VERSION 5.7 ;
  NOWIREEXTENSIONATPIN ON ;
  DIVIDERCHAR "/" ;
  BUSBITCHARS "[]" ;
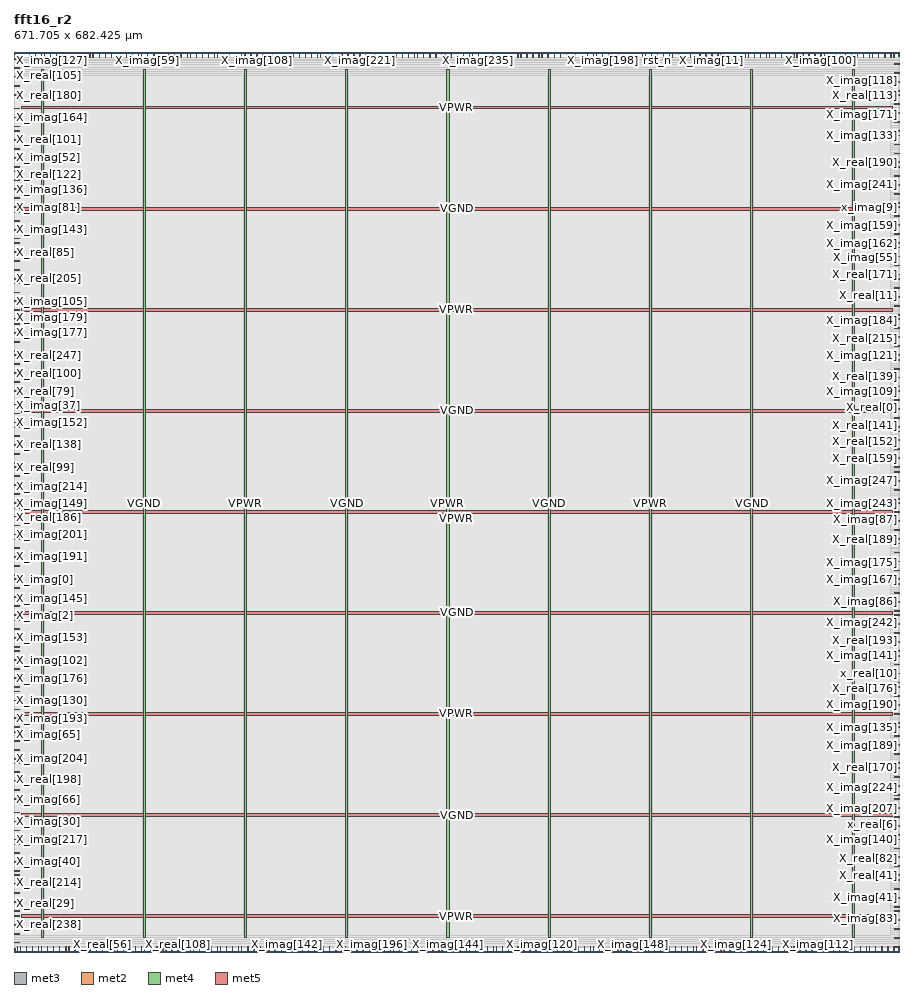
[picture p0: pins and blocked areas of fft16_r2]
MACRO fft16_r2
  CLASS BLOCK ;
  FOREIGN fft16_r2 ;
  ORIGIN 0.000 0.000 ;
  SIZE 671.705 BY 682.425 ;
  PIN X_imag[0]
    DIRECTION OUTPUT TRISTATE ;
    USE SIGNAL ;
    PORT
      LAYER met3 ;
        RECT 0.000 282.240 4.000 282.840 ;
    END
  END X_imag[0]
  PIN X_imag[100]
    DIRECTION OUTPUT TRISTATE ;
    USE SIGNAL ;
    PORT
      LAYER met2 ;
        RECT 611.890 678.425 612.170 682.425 ;
    END
  END X_imag[100]
  PIN X_imag[101]
    DIRECTION OUTPUT TRISTATE ;
    USE SIGNAL ;
    PORT
      LAYER met2 ;
        RECT 138.090 678.425 138.370 682.425 ;
    END
  END X_imag[101]
  PIN X_imag[102]
    DIRECTION OUTPUT TRISTATE ;
    USE SIGNAL ;
    PORT
      LAYER met3 ;
        RECT 0.000 221.040 4.000 221.640 ;
    END
  END X_imag[102]
  PIN X_imag[103]
    DIRECTION OUTPUT TRISTATE ;
    USE SIGNAL ;
    PORT
      LAYER met2 ;
        RECT 602.690 678.425 602.970 682.425 ;
    END
  END X_imag[103]
  PIN X_imag[104]
    DIRECTION OUTPUT TRISTATE ;
    USE SIGNAL ;
    PORT
      LAYER met3 ;
        RECT 667.705 34.040 671.705 34.640 ;
    END
  END X_imag[104]
  PIN X_imag[105]
    DIRECTION OUTPUT TRISTATE ;
    USE SIGNAL ;
    PORT
      LAYER met3 ;
        RECT 0.000 493.040 4.000 493.640 ;
    END
  END X_imag[105]
  PIN X_imag[106]
    DIRECTION OUTPUT TRISTATE ;
    USE SIGNAL ;
    PORT
      LAYER met2 ;
        RECT 154.190 0.000 154.470 4.000 ;
    END
  END X_imag[106]
  PIN X_imag[107]
    DIRECTION OUTPUT TRISTATE ;
    USE SIGNAL ;
    PORT
      LAYER met2 ;
        RECT 526.790 0.000 527.070 4.000 ;
    END
  END X_imag[107]
  PIN X_imag[108]
    DIRECTION OUTPUT TRISTATE ;
    USE SIGNAL ;
    PORT
      LAYER met2 ;
        RECT 184.090 678.425 184.370 682.425 ;
    END
  END X_imag[108]
  PIN X_imag[109]
    DIRECTION OUTPUT TRISTATE ;
    USE SIGNAL ;
    PORT
      LAYER met3 ;
        RECT 667.705 425.040 671.705 425.640 ;
    END
  END X_imag[109]
  PIN X_imag[10]
    DIRECTION OUTPUT TRISTATE ;
    USE SIGNAL ;
    PORT
      LAYER met2 ;
        RECT 204.790 678.425 205.070 682.425 ;
    END
  END X_imag[10]
  PIN X_imag[110]
    DIRECTION OUTPUT TRISTATE ;
    USE SIGNAL ;
    PORT
      LAYER met2 ;
        RECT 151.890 678.425 152.170 682.425 ;
    END
  END X_imag[110]
  PIN X_imag[111]
    DIRECTION OUTPUT TRISTATE ;
    USE SIGNAL ;
    PORT
      LAYER met2 ;
        RECT 218.590 0.000 218.870 4.000 ;
    END
  END X_imag[111]
  PIN X_imag[112]
    DIRECTION OUTPUT TRISTATE ;
    USE SIGNAL ;
    PORT
      LAYER met2 ;
        RECT 609.590 0.000 609.870 4.000 ;
    END
  END X_imag[112]
  PIN X_imag[113]
    DIRECTION OUTPUT TRISTATE ;
    USE SIGNAL ;
    PORT
      LAYER met2 ;
        RECT 225.490 678.425 225.770 682.425 ;
    END
  END X_imag[113]
  PIN X_imag[114]
    DIRECTION OUTPUT TRISTATE ;
    USE SIGNAL ;
    PORT
      LAYER met2 ;
        RECT 646.390 0.000 646.670 4.000 ;
    END
  END X_imag[114]
  PIN X_imag[115]
    DIRECTION OUTPUT TRISTATE ;
    USE SIGNAL ;
    PORT
      LAYER met2 ;
        RECT 96.690 678.425 96.970 682.425 ;
    END
  END X_imag[115]
  PIN X_imag[116]
    DIRECTION OUTPUT TRISTATE ;
    USE SIGNAL ;
    PORT
      LAYER met2 ;
        RECT 236.990 678.425 237.270 682.425 ;
    END
  END X_imag[116]
  PIN X_imag[117]
    DIRECTION OUTPUT TRISTATE ;
    USE SIGNAL ;
    PORT
      LAYER met2 ;
        RECT 476.190 678.425 476.470 682.425 ;
    END
  END X_imag[117]
  PIN X_imag[118]
    DIRECTION OUTPUT TRISTATE ;
    USE SIGNAL ;
    PORT
      LAYER met3 ;
        RECT 667.705 666.440 671.705 667.040 ;
    END
  END X_imag[118]
  PIN X_imag[119]
    DIRECTION OUTPUT TRISTATE ;
    USE SIGNAL ;
    PORT
      LAYER met2 ;
        RECT 430.190 678.425 430.470 682.425 ;
    END
  END X_imag[119]
  PIN X_imag[11]
    DIRECTION OUTPUT TRISTATE ;
    USE SIGNAL ;
    PORT
      LAYER met2 ;
        RECT 529.090 678.425 529.370 682.425 ;
    END
  END X_imag[11]
  PIN X_imag[120]
    DIRECTION OUTPUT TRISTATE ;
    USE SIGNAL ;
    PORT
      LAYER met2 ;
        RECT 400.290 0.000 400.570 4.000 ;
    END
  END X_imag[120]
  PIN X_imag[121]
    DIRECTION OUTPUT TRISTATE ;
    USE SIGNAL ;
    PORT
      LAYER met3 ;
        RECT 667.705 452.240 671.705 452.840 ;
    END
  END X_imag[121]
  PIN X_imag[122]
    DIRECTION OUTPUT TRISTATE ;
    USE SIGNAL ;
    PORT
      LAYER met2 ;
        RECT 515.290 678.425 515.570 682.425 ;
    END
  END X_imag[122]
  PIN X_imag[123]
    DIRECTION OUTPUT TRISTATE ;
    USE SIGNAL ;
    PORT
      LAYER met2 ;
        RECT 554.390 0.000 554.670 4.000 ;
    END
  END X_imag[123]
  PIN X_imag[124]
    DIRECTION OUTPUT TRISTATE ;
    USE SIGNAL ;
    PORT
      LAYER met2 ;
        RECT 547.490 0.000 547.770 4.000 ;
    END
  END X_imag[124]
  PIN X_imag[125]
    DIRECTION OUTPUT TRISTATE ;
    USE SIGNAL ;
    PORT
      LAYER met2 ;
        RECT 499.190 678.425 499.470 682.425 ;
    END
  END X_imag[125]
  PIN X_imag[126]
    DIRECTION OUTPUT TRISTATE ;
    USE SIGNAL ;
    PORT
      LAYER met3 ;
        RECT 667.705 47.640 671.705 48.240 ;
    END
  END X_imag[126]
  PIN X_imag[127]
    DIRECTION OUTPUT TRISTATE ;
    USE SIGNAL ;
    PORT
      LAYER met2 ;
        RECT 16.190 678.425 16.470 682.425 ;
    END
  END X_imag[127]
  PIN X_imag[128]
    DIRECTION OUTPUT TRISTATE ;
    USE SIGNAL ;
    PORT
      LAYER met2 ;
        RECT 439.390 678.425 439.670 682.425 ;
    END
  END X_imag[128]
  PIN X_imag[129]
    DIRECTION OUTPUT TRISTATE ;
    USE SIGNAL ;
    PORT
      LAYER met3 ;
        RECT 667.705 95.240 671.705 95.840 ;
    END
  END X_imag[129]
  PIN X_imag[12]
    DIRECTION OUTPUT TRISTATE ;
    USE SIGNAL ;
    PORT
      LAYER met2 ;
        RECT 2.390 678.425 2.670 682.425 ;
    END
  END X_imag[12]
  PIN X_imag[130]
    DIRECTION OUTPUT TRISTATE ;
    USE SIGNAL ;
    PORT
      LAYER met3 ;
        RECT 0.000 190.440 4.000 191.040 ;
    END
  END X_imag[130]
  PIN X_imag[131]
    DIRECTION OUTPUT TRISTATE ;
    USE SIGNAL ;
    PORT
      LAYER met3 ;
        RECT 0.000 105.440 4.000 106.040 ;
    END
  END X_imag[131]
  PIN X_imag[132]
    DIRECTION OUTPUT TRISTATE ;
    USE SIGNAL ;
    PORT
      LAYER met2 ;
        RECT 496.890 678.425 497.170 682.425 ;
    END
  END X_imag[132]
  PIN X_imag[133]
    DIRECTION OUTPUT TRISTATE ;
    USE SIGNAL ;
    PORT
      LAYER met3 ;
        RECT 667.705 618.840 671.705 619.440 ;
    END
  END X_imag[133]
  PIN X_imag[134]
    DIRECTION OUTPUT TRISTATE ;
    USE SIGNAL ;
    PORT
      LAYER met2 ;
        RECT 255.390 0.000 255.670 4.000 ;
    END
  END X_imag[134]
  PIN X_imag[135]
    DIRECTION OUTPUT TRISTATE ;
    USE SIGNAL ;
    PORT
      LAYER met3 ;
        RECT 667.705 170.040 671.705 170.640 ;
    END
  END X_imag[135]
  PIN X_imag[136]
    DIRECTION OUTPUT TRISTATE ;
    USE SIGNAL ;
    PORT
      LAYER met3 ;
        RECT 0.000 578.040 4.000 578.640 ;
    END
  END X_imag[136]
  PIN X_imag[137]
    DIRECTION OUTPUT TRISTATE ;
    USE SIGNAL ;
    PORT
      LAYER met2 ;
        RECT 572.790 0.000 573.070 4.000 ;
    END
  END X_imag[137]
  PIN X_imag[138]
    DIRECTION OUTPUT TRISTATE ;
    USE SIGNAL ;
    PORT
      LAYER met2 ;
        RECT 167.990 678.425 168.270 682.425 ;
    END
  END X_imag[138]
  PIN X_imag[139]
    DIRECTION OUTPUT TRISTATE ;
    USE SIGNAL ;
    PORT
      LAYER met2 ;
        RECT 190.990 678.425 191.270 682.425 ;
    END
  END X_imag[139]
  PIN X_imag[13]
    DIRECTION OUTPUT TRISTATE ;
    USE SIGNAL ;
    PORT
      LAYER met3 ;
        RECT 667.705 652.840 671.705 653.440 ;
    END
  END X_imag[13]
  PIN X_imag[140]
    DIRECTION OUTPUT TRISTATE ;
    USE SIGNAL ;
    PORT
      LAYER met3 ;
        RECT 667.705 85.040 671.705 85.640 ;
    END
  END X_imag[140]
  PIN X_imag[141]
    DIRECTION OUTPUT TRISTATE ;
    USE SIGNAL ;
    PORT
      LAYER met3 ;
        RECT 667.705 224.440 671.705 225.040 ;
    END
  END X_imag[141]
  PIN X_imag[142]
    DIRECTION OUTPUT TRISTATE ;
    USE SIGNAL ;
    PORT
      LAYER met2 ;
        RECT 207.090 0.000 207.370 4.000 ;
    END
  END X_imag[142]
  PIN X_imag[143]
    DIRECTION OUTPUT TRISTATE ;
    USE SIGNAL ;
    PORT
      LAYER met3 ;
        RECT 0.000 547.440 4.000 548.040 ;
    END
  END X_imag[143]
  PIN X_imag[144]
    DIRECTION OUTPUT TRISTATE ;
    USE SIGNAL ;
    PORT
      LAYER met2 ;
        RECT 328.990 0.000 329.270 4.000 ;
    END
  END X_imag[144]
  PIN X_imag[145]
    DIRECTION OUTPUT TRISTATE ;
    USE SIGNAL ;
    PORT
      LAYER met3 ;
        RECT 0.000 261.840 4.000 262.440 ;
    END
  END X_imag[145]
  PIN X_imag[146]
    DIRECTION OUTPUT TRISTATE ;
    USE SIGNAL ;
    PORT
      LAYER met3 ;
        RECT 667.705 574.640 671.705 575.240 ;
    END
  END X_imag[146]
  PIN X_imag[147]
    DIRECTION OUTPUT TRISTATE ;
    USE SIGNAL ;
    PORT
      LAYER met2 ;
        RECT 230.090 678.425 230.370 682.425 ;
    END
  END X_imag[147]
  PIN X_imag[148]
    DIRECTION OUTPUT TRISTATE ;
    USE SIGNAL ;
    PORT
      LAYER met2 ;
        RECT 469.290 0.000 469.570 4.000 ;
    END
  END X_imag[148]
  PIN X_imag[149]
    DIRECTION OUTPUT TRISTATE ;
    USE SIGNAL ;
    PORT
      LAYER met3 ;
        RECT 0.000 340.040 4.000 340.640 ;
    END
  END X_imag[149]
  PIN X_imag[14]
    DIRECTION OUTPUT TRISTATE ;
    USE SIGNAL ;
    PORT
      LAYER met2 ;
        RECT 425.590 678.425 425.870 682.425 ;
    END
  END X_imag[14]
  PIN X_imag[150]
    DIRECTION OUTPUT TRISTATE ;
    USE SIGNAL ;
    PORT
      LAYER met2 ;
        RECT 627.990 678.425 628.270 682.425 ;
    END
  END X_imag[150]
  PIN X_imag[151]
    DIRECTION OUTPUT TRISTATE ;
    USE SIGNAL ;
    PORT
      LAYER met3 ;
        RECT 667.705 588.240 671.705 588.840 ;
    END
  END X_imag[151]
  PIN X_imag[152]
    DIRECTION OUTPUT TRISTATE ;
    USE SIGNAL ;
    PORT
      LAYER met3 ;
        RECT 0.000 401.240 4.000 401.840 ;
    END
  END X_imag[152]
  PIN X_imag[153]
    DIRECTION OUTPUT TRISTATE ;
    USE SIGNAL ;
    PORT
      LAYER met3 ;
        RECT 0.000 238.040 4.000 238.640 ;
    END
  END X_imag[153]
  PIN X_imag[154]
    DIRECTION OUTPUT TRISTATE ;
    USE SIGNAL ;
    PORT
      LAYER met2 ;
        RECT 32.290 678.425 32.570 682.425 ;
    END
  END X_imag[154]
  PIN X_imag[155]
    DIRECTION OUTPUT TRISTATE ;
    USE SIGNAL ;
    PORT
      LAYER met2 ;
        RECT 248.490 0.000 248.770 4.000 ;
    END
  END X_imag[155]
  PIN X_imag[156]
    DIRECTION OUTPUT TRISTATE ;
    USE SIGNAL ;
    PORT
      LAYER met2 ;
        RECT 496.890 0.000 497.170 4.000 ;
    END
  END X_imag[156]
  PIN X_imag[157]
    DIRECTION OUTPUT TRISTATE ;
    USE SIGNAL ;
    PORT
      LAYER met3 ;
        RECT 0.000 122.440 4.000 123.040 ;
    END
  END X_imag[157]
  PIN X_imag[158]
    DIRECTION OUTPUT TRISTATE ;
    USE SIGNAL ;
    PORT
      LAYER met2 ;
        RECT 133.490 0.000 133.770 4.000 ;
    END
  END X_imag[158]
  PIN X_imag[159]
    DIRECTION OUTPUT TRISTATE ;
    USE SIGNAL ;
    PORT
      LAYER met3 ;
        RECT 667.705 550.840 671.705 551.440 ;
    END
  END X_imag[159]
  PIN X_imag[15]
    DIRECTION OUTPUT TRISTATE ;
    USE SIGNAL ;
    PORT
      LAYER met2 ;
        RECT 6.990 678.425 7.270 682.425 ;
    END
  END X_imag[15]
  PIN X_imag[160]
    DIRECTION OUTPUT TRISTATE ;
    USE SIGNAL ;
    PORT
      LAYER met2 ;
        RECT 614.190 678.425 614.470 682.425 ;
    END
  END X_imag[160]
  PIN X_imag[161]
    DIRECTION OUTPUT TRISTATE ;
    USE SIGNAL ;
    PORT
      LAYER met3 ;
        RECT 667.705 71.440 671.705 72.040 ;
    END
  END X_imag[161]
  PIN X_imag[162]
    DIRECTION OUTPUT TRISTATE ;
    USE SIGNAL ;
    PORT
      LAYER met3 ;
        RECT 667.705 537.240 671.705 537.840 ;
    END
  END X_imag[162]
  PIN X_imag[163]
    DIRECTION OUTPUT TRISTATE ;
    USE SIGNAL ;
    PORT
      LAYER met3 ;
        RECT 667.705 3.440 671.705 4.040 ;
    END
  END X_imag[163]
  PIN X_imag[164]
    DIRECTION OUTPUT TRISTATE ;
    USE SIGNAL ;
    PORT
      LAYER met3 ;
        RECT 0.000 632.440 4.000 633.040 ;
    END
  END X_imag[164]
  PIN X_imag[165]
    DIRECTION OUTPUT TRISTATE ;
    USE SIGNAL ;
    PORT
      LAYER met2 ;
        RECT 540.590 678.425 540.870 682.425 ;
    END
  END X_imag[165]
  PIN X_imag[166]
    DIRECTION OUTPUT TRISTATE ;
    USE SIGNAL ;
    PORT
      LAYER met2 ;
        RECT 494.590 0.000 494.870 4.000 ;
    END
  END X_imag[166]
  PIN X_imag[167]
    DIRECTION OUTPUT TRISTATE ;
    USE SIGNAL ;
    PORT
      LAYER met3 ;
        RECT 667.705 282.240 671.705 282.840 ;
    END
  END X_imag[167]
  PIN X_imag[168]
    DIRECTION OUTPUT TRISTATE ;
    USE SIGNAL ;
    PORT
      LAYER met2 ;
        RECT 418.690 678.425 418.970 682.425 ;
    END
  END X_imag[168]
  PIN X_imag[169]
    DIRECTION OUTPUT TRISTATE ;
    USE SIGNAL ;
    PORT
      LAYER met3 ;
        RECT 667.705 78.240 671.705 78.840 ;
    END
  END X_imag[169]
  PIN X_imag[16]
    DIRECTION OUTPUT TRISTATE ;
    USE SIGNAL ;
    PORT
      LAYER met3 ;
        RECT 667.705 448.840 671.705 449.440 ;
    END
  END X_imag[16]
  PIN X_imag[170]
    DIRECTION OUTPUT TRISTATE ;
    USE SIGNAL ;
    PORT
      LAYER met2 ;
        RECT 568.190 0.000 568.470 4.000 ;
    END
  END X_imag[170]
  PIN X_imag[171]
    DIRECTION OUTPUT TRISTATE ;
    USE SIGNAL ;
    PORT
      LAYER met3 ;
        RECT 667.705 629.040 671.705 629.640 ;
    END
  END X_imag[171]
  PIN X_imag[172]
    DIRECTION OUTPUT TRISTATE ;
    USE SIGNAL ;
    PORT
      LAYER met2 ;
        RECT 158.790 678.425 159.070 682.425 ;
    END
  END X_imag[172]
  PIN X_imag[173]
    DIRECTION OUTPUT TRISTATE ;
    USE SIGNAL ;
    PORT
      LAYER met3 ;
        RECT 667.705 10.240 671.705 10.840 ;
    END
  END X_imag[173]
  PIN X_imag[174]
    DIRECTION OUTPUT TRISTATE ;
    USE SIGNAL ;
    PORT
      LAYER met2 ;
        RECT 664.790 678.425 665.070 682.425 ;
    END
  END X_imag[174]
  PIN X_imag[175]
    DIRECTION OUTPUT TRISTATE ;
    USE SIGNAL ;
    PORT
      LAYER met3 ;
        RECT 667.705 289.040 671.705 289.640 ;
    END
  END X_imag[175]
  PIN X_imag[176]
    DIRECTION OUTPUT TRISTATE ;
    USE SIGNAL ;
    PORT
      LAYER met3 ;
        RECT 0.000 207.440 4.000 208.040 ;
    END
  END X_imag[176]
  PIN X_imag[177]
    DIRECTION OUTPUT TRISTATE ;
    USE SIGNAL ;
    PORT
      LAYER met3 ;
        RECT 0.000 469.240 4.000 469.840 ;
    END
  END X_imag[177]
  PIN X_imag[178]
    DIRECTION OUTPUT TRISTATE ;
    USE SIGNAL ;
    PORT
      LAYER met2 ;
        RECT 20.790 0.000 21.070 4.000 ;
    END
  END X_imag[178]
  PIN X_imag[179]
    DIRECTION OUTPUT TRISTATE ;
    USE SIGNAL ;
    PORT
      LAYER met3 ;
        RECT 0.000 486.240 4.000 486.840 ;
    END
  END X_imag[179]
  PIN X_imag[17]
    DIRECTION OUTPUT TRISTATE ;
    USE SIGNAL ;
    PORT
      LAYER met2 ;
        RECT 257.690 678.425 257.970 682.425 ;
    END
  END X_imag[17]
  PIN X_imag[180]
    DIRECTION OUTPUT TRISTATE ;
    USE SIGNAL ;
    PORT
      LAYER met3 ;
        RECT 667.705 527.040 671.705 527.640 ;
    END
  END X_imag[180]
  PIN X_imag[181]
    DIRECTION OUTPUT TRISTATE ;
    USE SIGNAL ;
    PORT
      LAYER met3 ;
        RECT 0.000 61.240 4.000 61.840 ;
    END
  END X_imag[181]
  PIN X_imag[182]
    DIRECTION OUTPUT TRISTATE ;
    USE SIGNAL ;
    PORT
      LAYER met3 ;
        RECT 667.705 622.240 671.705 622.840 ;
    END
  END X_imag[182]
  PIN X_imag[183]
    DIRECTION OUTPUT TRISTATE ;
    USE SIGNAL ;
    PORT
      LAYER met3 ;
        RECT 0.000 455.640 4.000 456.240 ;
    END
  END X_imag[183]
  PIN X_imag[184]
    DIRECTION OUTPUT TRISTATE ;
    USE SIGNAL ;
    PORT
      LAYER met3 ;
        RECT 667.705 472.640 671.705 473.240 ;
    END
  END X_imag[184]
  PIN X_imag[185]
    DIRECTION OUTPUT TRISTATE ;
    USE SIGNAL ;
    PORT
      LAYER met3 ;
        RECT 667.705 149.640 671.705 150.240 ;
    END
  END X_imag[185]
  PIN X_imag[186]
    DIRECTION OUTPUT TRISTATE ;
    USE SIGNAL ;
    PORT
      LAYER met2 ;
        RECT 230.090 0.000 230.370 4.000 ;
    END
  END X_imag[186]
  PIN X_imag[187]
    DIRECTION OUTPUT TRISTATE ;
    USE SIGNAL ;
    PORT
      LAYER met2 ;
        RECT 356.590 678.425 356.870 682.425 ;
    END
  END X_imag[187]
  PIN X_imag[188]
    DIRECTION OUTPUT TRISTATE ;
    USE SIGNAL ;
    PORT
      LAYER met2 ;
        RECT 241.590 678.425 241.870 682.425 ;
    END
  END X_imag[188]
  PIN X_imag[189]
    DIRECTION OUTPUT TRISTATE ;
    USE SIGNAL ;
    PORT
      LAYER met3 ;
        RECT 667.705 156.440 671.705 157.040 ;
    END
  END X_imag[189]
  PIN X_imag[18]
    DIRECTION OUTPUT TRISTATE ;
    USE SIGNAL ;
    PORT
      LAYER met2 ;
        RECT 20.790 678.425 21.070 682.425 ;
    END
  END X_imag[18]
  PIN X_imag[190]
    DIRECTION OUTPUT TRISTATE ;
    USE SIGNAL ;
    PORT
      LAYER met3 ;
        RECT 667.705 187.040 671.705 187.640 ;
    END
  END X_imag[190]
  PIN X_imag[191]
    DIRECTION OUTPUT TRISTATE ;
    USE SIGNAL ;
    PORT
      LAYER met3 ;
        RECT 0.000 299.240 4.000 299.840 ;
    END
  END X_imag[191]
  PIN X_imag[192]
    DIRECTION OUTPUT TRISTATE ;
    USE SIGNAL ;
    PORT
      LAYER met3 ;
        RECT 0.000 499.840 4.000 500.440 ;
    END
  END X_imag[192]
  PIN X_imag[193]
    DIRECTION OUTPUT TRISTATE ;
    USE SIGNAL ;
    PORT
      LAYER met3 ;
        RECT 0.000 176.840 4.000 177.440 ;
    END
  END X_imag[193]
  PIN X_imag[194]
    DIRECTION OUTPUT TRISTATE ;
    USE SIGNAL ;
    PORT
      LAYER met2 ;
        RECT 69.090 678.425 69.370 682.425 ;
    END
  END X_imag[194]
  PIN X_imag[195]
    DIRECTION OUTPUT TRISTATE ;
    USE SIGNAL ;
    PORT
      LAYER met3 ;
        RECT 667.705 180.240 671.705 180.840 ;
    END
  END X_imag[195]
  PIN X_imag[196]
    DIRECTION OUTPUT TRISTATE ;
    USE SIGNAL ;
    PORT
      LAYER met2 ;
        RECT 271.490 0.000 271.770 4.000 ;
    END
  END X_imag[196]
  PIN X_imag[197]
    DIRECTION OUTPUT TRISTATE ;
    USE SIGNAL ;
    PORT
      LAYER met2 ;
        RECT 464.690 0.000 464.970 4.000 ;
    END
  END X_imag[197]
  PIN X_imag[198]
    DIRECTION OUTPUT TRISTATE ;
    USE SIGNAL ;
    PORT
      LAYER met2 ;
        RECT 446.290 678.425 446.570 682.425 ;
    END
  END X_imag[198]
  PIN X_imag[199]
    DIRECTION OUTPUT TRISTATE ;
    USE SIGNAL ;
    PORT
      LAYER met2 ;
        RECT 453.190 0.000 453.470 4.000 ;
    END
  END X_imag[199]
  PIN X_imag[19]
    DIRECTION OUTPUT TRISTATE ;
    USE SIGNAL ;
    PORT
      LAYER met2 ;
        RECT 397.990 678.425 398.270 682.425 ;
    END
  END X_imag[19]
  PIN X_imag[1]
    DIRECTION OUTPUT TRISTATE ;
    USE SIGNAL ;
    PORT
      LAYER met2 ;
        RECT 634.890 678.425 635.170 682.425 ;
    END
  END X_imag[1]
  PIN X_imag[200]
    DIRECTION OUTPUT TRISTATE ;
    USE SIGNAL ;
    PORT
      LAYER met2 ;
        RECT 512.990 678.425 513.270 682.425 ;
    END
  END X_imag[200]
  PIN X_imag[201]
    DIRECTION OUTPUT TRISTATE ;
    USE SIGNAL ;
    PORT
      LAYER met3 ;
        RECT 0.000 316.240 4.000 316.840 ;
    END
  END X_imag[201]
  PIN X_imag[202]
    DIRECTION OUTPUT TRISTATE ;
    USE SIGNAL ;
    PORT
      LAYER met2 ;
        RECT 13.890 0.000 14.170 4.000 ;
    END
  END X_imag[202]
  PIN X_imag[203]
    DIRECTION OUTPUT TRISTATE ;
    USE SIGNAL ;
    PORT
      LAYER met2 ;
        RECT 4.690 0.000 4.970 4.000 ;
    END
  END X_imag[203]
  PIN X_imag[204]
    DIRECTION OUTPUT TRISTATE ;
    USE SIGNAL ;
    PORT
      LAYER met3 ;
        RECT 0.000 146.240 4.000 146.840 ;
    END
  END X_imag[204]
  PIN X_imag[205]
    DIRECTION OUTPUT TRISTATE ;
    USE SIGNAL ;
    PORT
      LAYER met2 ;
        RECT 269.190 0.000 269.470 4.000 ;
    END
  END X_imag[205]
  PIN X_imag[206]
    DIRECTION OUTPUT TRISTATE ;
    USE SIGNAL ;
    PORT
      LAYER met3 ;
        RECT 0.000 37.440 4.000 38.040 ;
    END
  END X_imag[206]
  PIN X_imag[207]
    DIRECTION OUTPUT TRISTATE ;
    USE SIGNAL ;
    PORT
      LAYER met3 ;
        RECT 667.705 108.840 671.705 109.440 ;
    END
  END X_imag[207]
  PIN X_imag[208]
    DIRECTION OUTPUT TRISTATE ;
    USE SIGNAL ;
    PORT
      LAYER met3 ;
        RECT 667.705 411.440 671.705 412.040 ;
    END
  END X_imag[208]
  PIN X_imag[209]
    DIRECTION OUTPUT TRISTATE ;
    USE SIGNAL ;
    PORT
      LAYER met2 ;
        RECT 115.090 0.000 115.370 4.000 ;
    END
  END X_imag[209]
  PIN X_imag[20]
    DIRECTION OUTPUT TRISTATE ;
    USE SIGNAL ;
    PORT
      LAYER met2 ;
        RECT 161.090 0.000 161.370 4.000 ;
    END
  END X_imag[20]
  PIN X_imag[210]
    DIRECTION OUTPUT TRISTATE ;
    USE SIGNAL ;
    PORT
      LAYER met2 ;
        RECT 195.590 678.425 195.870 682.425 ;
    END
  END X_imag[210]
  PIN X_imag[211]
    DIRECTION OUTPUT TRISTATE ;
    USE SIGNAL ;
    PORT
      LAYER met2 ;
        RECT 420.990 678.425 421.270 682.425 ;
    END
  END X_imag[211]
  PIN X_imag[212]
    DIRECTION OUTPUT TRISTATE ;
    USE SIGNAL ;
    PORT
      LAYER met3 ;
        RECT 667.705 428.440 671.705 429.040 ;
    END
  END X_imag[212]
  PIN X_imag[213]
    DIRECTION OUTPUT TRISTATE ;
    USE SIGNAL ;
    PORT
      LAYER met3 ;
        RECT 0.000 336.640 4.000 337.240 ;
    END
  END X_imag[213]
  PIN X_imag[214]
    DIRECTION OUTPUT TRISTATE ;
    USE SIGNAL ;
    PORT
      LAYER met3 ;
        RECT 0.000 346.840 4.000 347.440 ;
    END
  END X_imag[214]
  PIN X_imag[215]
    DIRECTION OUTPUT TRISTATE ;
    USE SIGNAL ;
    PORT
      LAYER met2 ;
        RECT 117.390 678.425 117.670 682.425 ;
    END
  END X_imag[215]
  PIN X_imag[216]
    DIRECTION OUTPUT TRISTATE ;
    USE SIGNAL ;
    PORT
      LAYER met2 ;
        RECT 549.790 678.425 550.070 682.425 ;
    END
  END X_imag[216]
  PIN X_imag[217]
    DIRECTION OUTPUT TRISTATE ;
    USE SIGNAL ;
    PORT
      LAYER met3 ;
        RECT 0.000 85.040 4.000 85.640 ;
    END
  END X_imag[217]
  PIN X_imag[218]
    DIRECTION OUTPUT TRISTATE ;
    USE SIGNAL ;
    PORT
      LAYER met3 ;
        RECT 0.000 275.440 4.000 276.040 ;
    END
  END X_imag[218]
  PIN X_imag[219]
    DIRECTION OUTPUT TRISTATE ;
    USE SIGNAL ;
    PORT
      LAYER met2 ;
        RECT 558.990 0.000 559.270 4.000 ;
    END
  END X_imag[219]
  PIN X_imag[21]
    DIRECTION OUTPUT TRISTATE ;
    USE SIGNAL ;
    PORT
      LAYER met3 ;
        RECT 667.705 510.040 671.705 510.640 ;
    END
  END X_imag[21]
  PIN X_imag[220]
    DIRECTION OUTPUT TRISTATE ;
    USE SIGNAL ;
    PORT
      LAYER met3 ;
        RECT 0.000 329.840 4.000 330.440 ;
    END
  END X_imag[220]
  PIN X_imag[221]
    DIRECTION OUTPUT TRISTATE ;
    USE SIGNAL ;
    PORT
      LAYER met2 ;
        RECT 262.290 678.425 262.570 682.425 ;
    END
  END X_imag[221]
  PIN X_imag[222]
    DIRECTION OUTPUT TRISTATE ;
    USE SIGNAL ;
    PORT
      LAYER met2 ;
        RECT 259.990 0.000 260.270 4.000 ;
    END
  END X_imag[222]
  PIN X_imag[223]
    DIRECTION OUTPUT TRISTATE ;
    USE SIGNAL ;
    PORT
      LAYER met2 ;
        RECT 324.390 678.425 324.670 682.425 ;
    END
  END X_imag[223]
  PIN X_imag[224]
    DIRECTION OUTPUT TRISTATE ;
    USE SIGNAL ;
    PORT
      LAYER met3 ;
        RECT 667.705 119.040 671.705 119.640 ;
    END
  END X_imag[224]
  PIN X_imag[225]
    DIRECTION OUTPUT TRISTATE ;
    USE SIGNAL ;
    PORT
      LAYER met3 ;
        RECT 667.705 23.840 671.705 24.440 ;
    END
  END X_imag[225]
  PIN X_imag[226]
    DIRECTION OUTPUT TRISTATE ;
    USE SIGNAL ;
    PORT
      LAYER met2 ;
        RECT 188.690 678.425 188.970 682.425 ;
    END
  END X_imag[226]
  PIN X_imag[227]
    DIRECTION OUTPUT TRISTATE ;
    USE SIGNAL ;
    PORT
      LAYER met3 ;
        RECT 667.705 595.040 671.705 595.640 ;
    END
  END X_imag[227]
  PIN X_imag[228]
    DIRECTION OUTPUT TRISTATE ;
    USE SIGNAL ;
    PORT
      LAYER met2 ;
        RECT 384.190 678.425 384.470 682.425 ;
    END
  END X_imag[228]
  PIN X_imag[229]
    DIRECTION OUTPUT TRISTATE ;
    USE SIGNAL ;
    PORT
      LAYER met3 ;
        RECT 0.000 112.240 4.000 112.840 ;
    END
  END X_imag[229]
  PIN X_imag[22]
    DIRECTION OUTPUT TRISTATE ;
    USE SIGNAL ;
    PORT
      LAYER met3 ;
        RECT 0.000 312.840 4.000 313.440 ;
    END
  END X_imag[22]
  PIN X_imag[230]
    DIRECTION OUTPUT TRISTATE ;
    USE SIGNAL ;
    PORT
      LAYER met2 ;
        RECT 25.390 0.000 25.670 4.000 ;
    END
  END X_imag[230]
  PIN X_imag[231]
    DIRECTION OUTPUT TRISTATE ;
    USE SIGNAL ;
    PORT
      LAYER met2 ;
        RECT 455.490 678.425 455.770 682.425 ;
    END
  END X_imag[231]
  PIN X_imag[232]
    DIRECTION OUTPUT TRISTATE ;
    USE SIGNAL ;
    PORT
      LAYER met3 ;
        RECT 667.705 533.840 671.705 534.440 ;
    END
  END X_imag[232]
  PIN X_imag[233]
    DIRECTION OUTPUT TRISTATE ;
    USE SIGNAL ;
    PORT
      LAYER met2 ;
        RECT 285.290 0.000 285.570 4.000 ;
    END
  END X_imag[233]
  PIN X_imag[234]
    DIRECTION OUTPUT TRISTATE ;
    USE SIGNAL ;
    PORT
      LAYER met2 ;
        RECT 317.490 0.000 317.770 4.000 ;
    END
  END X_imag[234]
  PIN X_imag[235]
    DIRECTION OUTPUT TRISTATE ;
    USE SIGNAL ;
    PORT
      LAYER met2 ;
        RECT 351.990 678.425 352.270 682.425 ;
    END
  END X_imag[235]
  PIN X_imag[236]
    DIRECTION OUTPUT TRISTATE ;
    USE SIGNAL ;
    PORT
      LAYER met2 ;
        RECT 407.190 0.000 407.470 4.000 ;
    END
  END X_imag[236]
  PIN X_imag[237]
    DIRECTION OUTPUT TRISTATE ;
    USE SIGNAL ;
    PORT
      LAYER met2 ;
        RECT 2.390 0.000 2.670 4.000 ;
    END
  END X_imag[237]
  PIN X_imag[238]
    DIRECTION OUTPUT TRISTATE ;
    USE SIGNAL ;
    PORT
      LAYER met2 ;
        RECT 46.090 0.000 46.370 4.000 ;
    END
  END X_imag[238]
  PIN X_imag[239]
    DIRECTION OUTPUT TRISTATE ;
    USE SIGNAL ;
    PORT
      LAYER met2 ;
        RECT 96.690 0.000 96.970 4.000 ;
    END
  END X_imag[239]
  PIN X_imag[23]
    DIRECTION OUTPUT TRISTATE ;
    USE SIGNAL ;
    PORT
      LAYER met3 ;
        RECT 0.000 231.240 4.000 231.840 ;
    END
  END X_imag[23]
  PIN X_imag[240]
    DIRECTION OUTPUT TRISTATE ;
    USE SIGNAL ;
    PORT
      LAYER met3 ;
        RECT 0.000 6.840 4.000 7.440 ;
    END
  END X_imag[240]
  PIN X_imag[241]
    DIRECTION OUTPUT TRISTATE ;
    USE SIGNAL ;
    PORT
      LAYER met3 ;
        RECT 667.705 581.440 671.705 582.040 ;
    END
  END X_imag[241]
  PIN X_imag[242]
    DIRECTION OUTPUT TRISTATE ;
    USE SIGNAL ;
    PORT
      LAYER met3 ;
        RECT 667.705 255.040 671.705 255.640 ;
    END
  END X_imag[242]
  PIN X_imag[243]
    DIRECTION OUTPUT TRISTATE ;
    USE SIGNAL ;
    PORT
      LAYER met3 ;
        RECT 667.705 340.040 671.705 340.640 ;
    END
  END X_imag[243]
  PIN X_imag[244]
    DIRECTION OUTPUT TRISTATE ;
    USE SIGNAL ;
    PORT
      LAYER met2 ;
        RECT 73.690 678.425 73.970 682.425 ;
    END
  END X_imag[244]
  PIN X_imag[245]
    DIRECTION OUTPUT TRISTATE ;
    USE SIGNAL ;
    PORT
      LAYER met2 ;
        RECT 630.290 0.000 630.570 4.000 ;
    END
  END X_imag[245]
  PIN X_imag[246]
    DIRECTION OUTPUT TRISTATE ;
    USE SIGNAL ;
    PORT
      LAYER met3 ;
        RECT 667.705 479.440 671.705 480.040 ;
    END
  END X_imag[246]
  PIN X_imag[247]
    DIRECTION OUTPUT TRISTATE ;
    USE SIGNAL ;
    PORT
      LAYER met3 ;
        RECT 667.705 357.040 671.705 357.640 ;
    END
  END X_imag[247]
  PIN X_imag[248]
    DIRECTION OUTPUT TRISTATE ;
    USE SIGNAL ;
    PORT
      LAYER met2 ;
        RECT 211.690 0.000 211.970 4.000 ;
    END
  END X_imag[248]
  PIN X_imag[249]
    DIRECTION OUTPUT TRISTATE ;
    USE SIGNAL ;
    PORT
      LAYER met2 ;
        RECT 448.590 0.000 448.870 4.000 ;
    END
  END X_imag[249]
  PIN X_imag[24]
    DIRECTION OUTPUT TRISTATE ;
    USE SIGNAL ;
    PORT
      LAYER met2 ;
        RECT 200.190 678.425 200.470 682.425 ;
    END
  END X_imag[24]
  PIN X_imag[250]
    DIRECTION OUTPUT TRISTATE ;
    USE SIGNAL ;
    PORT
      LAYER met2 ;
        RECT 595.790 0.000 596.070 4.000 ;
    END
  END X_imag[250]
  PIN X_imag[251]
    DIRECTION OUTPUT TRISTATE ;
    USE SIGNAL ;
    PORT
      LAYER met2 ;
        RECT 331.290 678.425 331.570 682.425 ;
    END
  END X_imag[251]
  PIN X_imag[252]
    DIRECTION OUTPUT TRISTATE ;
    USE SIGNAL ;
    PORT
      LAYER met2 ;
        RECT 437.090 0.000 437.370 4.000 ;
    END
  END X_imag[252]
  PIN X_imag[253]
    DIRECTION OUTPUT TRISTATE ;
    USE SIGNAL ;
    PORT
      LAYER met2 ;
        RECT 319.790 678.425 320.070 682.425 ;
    END
  END X_imag[253]
  PIN X_imag[254]
    DIRECTION OUTPUT TRISTATE ;
    USE SIGNAL ;
    PORT
      LAYER met2 ;
        RECT 342.790 0.000 343.070 4.000 ;
    END
  END X_imag[254]
  PIN X_imag[255]
    DIRECTION OUTPUT TRISTATE ;
    USE SIGNAL ;
    PORT
      LAYER met2 ;
        RECT 607.290 678.425 607.570 682.425 ;
    END
  END X_imag[255]
  PIN X_imag[25]
    DIRECTION OUTPUT TRISTATE ;
    USE SIGNAL ;
    PORT
      LAYER met3 ;
        RECT 0.000 377.440 4.000 378.040 ;
    END
  END X_imag[25]
  PIN X_imag[26]
    DIRECTION OUTPUT TRISTATE ;
    USE SIGNAL ;
    PORT
      LAYER met3 ;
        RECT 0.000 51.040 4.000 51.640 ;
    END
  END X_imag[26]
  PIN X_imag[27]
    DIRECTION OUTPUT TRISTATE ;
    USE SIGNAL ;
    PORT
      LAYER met3 ;
        RECT 0.000 516.840 4.000 517.440 ;
    END
  END X_imag[27]
  PIN X_imag[28]
    DIRECTION OUTPUT TRISTATE ;
    USE SIGNAL ;
    PORT
      LAYER met2 ;
        RECT 333.590 0.000 333.870 4.000 ;
    END
  END X_imag[28]
  PIN X_imag[29]
    DIRECTION OUTPUT TRISTATE ;
    USE SIGNAL ;
    PORT
      LAYER met2 ;
        RECT 48.390 678.425 48.670 682.425 ;
    END
  END X_imag[29]
  PIN X_imag[2]
    DIRECTION OUTPUT TRISTATE ;
    USE SIGNAL ;
    PORT
      LAYER met3 ;
        RECT 0.000 255.040 4.000 255.640 ;
    END
  END X_imag[2]
  PIN X_imag[30]
    DIRECTION OUTPUT TRISTATE ;
    USE SIGNAL ;
    PORT
      LAYER met3 ;
        RECT 0.000 98.640 4.000 99.240 ;
    END
  END X_imag[30]
  PIN X_imag[31]
    DIRECTION OUTPUT TRISTATE ;
    USE SIGNAL ;
    PORT
      LAYER met2 ;
        RECT 301.390 0.000 301.670 4.000 ;
    END
  END X_imag[31]
  PIN X_imag[32]
    DIRECTION OUTPUT TRISTATE ;
    USE SIGNAL ;
    PORT
      LAYER met2 ;
        RECT 623.390 678.425 623.670 682.425 ;
    END
  END X_imag[32]
  PIN X_imag[33]
    DIRECTION OUTPUT TRISTATE ;
    USE SIGNAL ;
    PORT
      LAYER met2 ;
        RECT 473.890 0.000 474.170 4.000 ;
    END
  END X_imag[33]
  PIN X_imag[34]
    DIRECTION OUTPUT TRISTATE ;
    USE SIGNAL ;
    PORT
      LAYER met2 ;
        RECT 466.990 678.425 467.270 682.425 ;
    END
  END X_imag[34]
  PIN X_imag[35]
    DIRECTION OUTPUT TRISTATE ;
    USE SIGNAL ;
    PORT
      LAYER met2 ;
        RECT 517.590 0.000 517.870 4.000 ;
    END
  END X_imag[35]
  PIN X_imag[36]
    DIRECTION OUTPUT TRISTATE ;
    USE SIGNAL ;
    PORT
      LAYER met3 ;
        RECT 667.705 258.440 671.705 259.040 ;
    END
  END X_imag[36]
  PIN X_imag[37]
    DIRECTION OUTPUT TRISTATE ;
    USE SIGNAL ;
    PORT
      LAYER met3 ;
        RECT 0.000 408.040 4.000 408.640 ;
    END
  END X_imag[37]
  PIN X_imag[38]
    DIRECTION OUTPUT TRISTATE ;
    USE SIGNAL ;
    PORT
      LAYER met2 ;
        RECT 457.790 678.425 458.070 682.425 ;
    END
  END X_imag[38]
  PIN X_imag[39]
    DIRECTION OUTPUT TRISTATE ;
    USE SIGNAL ;
    PORT
      LAYER met2 ;
        RECT 232.390 678.425 232.670 682.425 ;
    END
  END X_imag[39]
  PIN X_imag[3]
    DIRECTION OUTPUT TRISTATE ;
    USE SIGNAL ;
    PORT
      LAYER met2 ;
        RECT 584.290 0.000 584.570 4.000 ;
    END
  END X_imag[3]
  PIN X_imag[40]
    DIRECTION OUTPUT TRISTATE ;
    USE SIGNAL ;
    PORT
      LAYER met3 ;
        RECT 0.000 68.040 4.000 68.640 ;
    END
  END X_imag[40]
  PIN X_imag[41]
    DIRECTION OUTPUT TRISTATE ;
    USE SIGNAL ;
    PORT
      LAYER met3 ;
        RECT 667.705 40.840 671.705 41.440 ;
    END
  END X_imag[41]
  PIN X_imag[42]
    DIRECTION OUTPUT TRISTATE ;
    USE SIGNAL ;
    PORT
      LAYER met2 ;
        RECT 80.590 678.425 80.870 682.425 ;
    END
  END X_imag[42]
  PIN X_imag[43]
    DIRECTION OUTPUT TRISTATE ;
    USE SIGNAL ;
    PORT
      LAYER met2 ;
        RECT 126.590 678.425 126.870 682.425 ;
    END
  END X_imag[43]
  PIN X_imag[44]
    DIRECTION OUTPUT TRISTATE ;
    USE SIGNAL ;
    PORT
      LAYER met3 ;
        RECT 0.000 540.640 4.000 541.240 ;
    END
  END X_imag[44]
  PIN X_imag[45]
    DIRECTION OUTPUT TRISTATE ;
    USE SIGNAL ;
    PORT
      LAYER met2 ;
        RECT 121.990 678.425 122.270 682.425 ;
    END
  END X_imag[45]
  PIN X_imag[46]
    DIRECTION OUTPUT TRISTATE ;
    USE SIGNAL ;
    PORT
      LAYER met3 ;
        RECT 0.000 476.040 4.000 476.640 ;
    END
  END X_imag[46]
  PIN X_imag[47]
    DIRECTION OUTPUT TRISTATE ;
    USE SIGNAL ;
    PORT
      LAYER met2 ;
        RECT 611.890 0.000 612.170 4.000 ;
    END
  END X_imag[47]
  PIN X_imag[48]
    DIRECTION OUTPUT TRISTATE ;
    USE SIGNAL ;
    PORT
      LAYER met2 ;
        RECT 381.890 0.000 382.170 4.000 ;
    END
  END X_imag[48]
  PIN X_imag[49]
    DIRECTION OUTPUT TRISTATE ;
    USE SIGNAL ;
    PORT
      LAYER met2 ;
        RECT 340.490 678.425 340.770 682.425 ;
    END
  END X_imag[49]
  PIN X_imag[4]
    DIRECTION OUTPUT TRISTATE ;
    USE SIGNAL ;
    PORT
      LAYER met3 ;
        RECT 667.705 248.240 671.705 248.840 ;
    END
  END X_imag[4]
  PIN X_imag[50]
    DIRECTION OUTPUT TRISTATE ;
    USE SIGNAL ;
    PORT
      LAYER met2 ;
        RECT 216.290 678.425 216.570 682.425 ;
    END
  END X_imag[50]
  PIN X_imag[51]
    DIRECTION OUTPUT TRISTATE ;
    USE SIGNAL ;
    PORT
      LAYER met2 ;
        RECT 462.390 678.425 462.670 682.425 ;
    END
  END X_imag[51]
  PIN X_imag[52]
    DIRECTION OUTPUT TRISTATE ;
    USE SIGNAL ;
    PORT
      LAYER met3 ;
        RECT 0.000 601.840 4.000 602.440 ;
    END
  END X_imag[52]
  PIN X_imag[53]
    DIRECTION OUTPUT TRISTATE ;
    USE SIGNAL ;
    PORT
      LAYER met2 ;
        RECT 287.590 678.425 287.870 682.425 ;
    END
  END X_imag[53]
  PIN X_imag[54]
    DIRECTION OUTPUT TRISTATE ;
    USE SIGNAL ;
    PORT
      LAYER met2 ;
        RECT 372.690 678.425 372.970 682.425 ;
    END
  END X_imag[54]
  PIN X_imag[55]
    DIRECTION OUTPUT TRISTATE ;
    USE SIGNAL ;
    PORT
      LAYER met3 ;
        RECT 667.705 520.240 671.705 520.840 ;
    END
  END X_imag[55]
  PIN X_imag[56]
    DIRECTION OUTPUT TRISTATE ;
    USE SIGNAL ;
    PORT
      LAYER met2 ;
        RECT 565.890 678.425 566.170 682.425 ;
    END
  END X_imag[56]
  PIN X_imag[57]
    DIRECTION OUTPUT TRISTATE ;
    USE SIGNAL ;
    PORT
      LAYER met2 ;
        RECT 326.690 678.425 326.970 682.425 ;
    END
  END X_imag[57]
  PIN X_imag[58]
    DIRECTION OUTPUT TRISTATE ;
    USE SIGNAL ;
    PORT
      LAYER met2 ;
        RECT 105.890 678.425 106.170 682.425 ;
    END
  END X_imag[58]
  PIN X_imag[59]
    DIRECTION OUTPUT TRISTATE ;
    USE SIGNAL ;
    PORT
      LAYER met2 ;
        RECT 101.290 678.425 101.570 682.425 ;
    END
  END X_imag[59]
  PIN X_imag[5]
    DIRECTION OUTPUT TRISTATE ;
    USE SIGNAL ;
    PORT
      LAYER met3 ;
        RECT 0.000 523.640 4.000 524.240 ;
    END
  END X_imag[5]
  PIN X_imag[60]
    DIRECTION OUTPUT TRISTATE ;
    USE SIGNAL ;
    PORT
      LAYER met2 ;
        RECT 570.490 678.425 570.770 682.425 ;
    END
  END X_imag[60]
  PIN X_imag[61]
    DIRECTION OUTPUT TRISTATE ;
    USE SIGNAL ;
    PORT
      LAYER met3 ;
        RECT 0.000 292.440 4.000 293.040 ;
    END
  END X_imag[61]
  PIN X_imag[62]
    DIRECTION OUTPUT TRISTATE ;
    USE SIGNAL ;
    PORT
      LAYER met3 ;
        RECT 667.705 659.640 671.705 660.240 ;
    END
  END X_imag[62]
  PIN X_imag[63]
    DIRECTION OUTPUT TRISTATE ;
    USE SIGNAL ;
    PORT
      LAYER met2 ;
        RECT 172.590 678.425 172.870 682.425 ;
    END
  END X_imag[63]
  PIN X_imag[64]
    DIRECTION OUTPUT TRISTATE ;
    USE SIGNAL ;
    PORT
      LAYER met2 ;
        RECT 57.590 0.000 57.870 4.000 ;
    END
  END X_imag[64]
  PIN X_imag[65]
    DIRECTION OUTPUT TRISTATE ;
    USE SIGNAL ;
    PORT
      LAYER met3 ;
        RECT 0.000 170.040 4.000 170.640 ;
    END
  END X_imag[65]
  PIN X_imag[66]
    DIRECTION OUTPUT TRISTATE ;
    USE SIGNAL ;
    PORT
      LAYER met3 ;
        RECT 0.000 115.640 4.000 116.240 ;
    END
  END X_imag[66]
  PIN X_imag[67]
    DIRECTION OUTPUT TRISTATE ;
    USE SIGNAL ;
    PORT
      LAYER met2 ;
        RECT 39.190 678.425 39.470 682.425 ;
    END
  END X_imag[67]
  PIN X_imag[68]
    DIRECTION OUTPUT TRISTATE ;
    USE SIGNAL ;
    PORT
      LAYER met2 ;
        RECT 358.890 0.000 359.170 4.000 ;
    END
  END X_imag[68]
  PIN X_imag[69]
    DIRECTION OUTPUT TRISTATE ;
    USE SIGNAL ;
    PORT
      LAYER met2 ;
        RECT 223.190 0.000 223.470 4.000 ;
    END
  END X_imag[69]
  PIN X_imag[6]
    DIRECTION OUTPUT TRISTATE ;
    USE SIGNAL ;
    PORT
      LAYER met2 ;
        RECT 363.490 678.425 363.770 682.425 ;
    END
  END X_imag[6]
  PIN X_imag[70]
    DIRECTION OUTPUT TRISTATE ;
    USE SIGNAL ;
    PORT
      LAYER met2 ;
        RECT 92.090 0.000 92.370 4.000 ;
    END
  END X_imag[70]
  PIN X_imag[71]
    DIRECTION OUTPUT TRISTATE ;
    USE SIGNAL ;
    PORT
      LAYER met2 ;
        RECT 657.890 0.000 658.170 4.000 ;
    END
  END X_imag[71]
  PIN X_imag[72]
    DIRECTION OUTPUT TRISTATE ;
    USE SIGNAL ;
    PORT
      LAYER met2 ;
        RECT 23.090 678.425 23.370 682.425 ;
    END
  END X_imag[72]
  PIN X_imag[73]
    DIRECTION OUTPUT TRISTATE ;
    USE SIGNAL ;
    PORT
      LAYER met2 ;
        RECT 404.890 678.425 405.170 682.425 ;
    END
  END X_imag[73]
  PIN X_imag[74]
    DIRECTION OUTPUT TRISTATE ;
    USE SIGNAL ;
    PORT
      LAYER met2 ;
        RECT 276.090 0.000 276.370 4.000 ;
    END
  END X_imag[74]
  PIN X_imag[75]
    DIRECTION OUTPUT TRISTATE ;
    USE SIGNAL ;
    PORT
      LAYER met2 ;
        RECT 388.790 678.425 389.070 682.425 ;
    END
  END X_imag[75]
  PIN X_imag[76]
    DIRECTION OUTPUT TRISTATE ;
    USE SIGNAL ;
    PORT
      LAYER met2 ;
        RECT 186.390 0.000 186.670 4.000 ;
    END
  END X_imag[76]
  PIN X_imag[77]
    DIRECTION OUTPUT TRISTATE ;
    USE SIGNAL ;
    PORT
      LAYER met2 ;
        RECT 43.790 678.425 44.070 682.425 ;
    END
  END X_imag[77]
  PIN X_imag[78]
    DIRECTION OUTPUT TRISTATE ;
    USE SIGNAL ;
    PORT
      LAYER met2 ;
        RECT 110.490 678.425 110.770 682.425 ;
    END
  END X_imag[78]
  PIN X_imag[79]
    DIRECTION OUTPUT TRISTATE ;
    USE SIGNAL ;
    PORT
      LAYER met2 ;
        RECT 492.290 678.425 492.570 682.425 ;
    END
  END X_imag[79]
  PIN X_imag[7]
    DIRECTION OUTPUT TRISTATE ;
    USE SIGNAL ;
    PORT
      LAYER met2 ;
        RECT 489.990 0.000 490.270 4.000 ;
    END
  END X_imag[7]
  PIN X_imag[80]
    DIRECTION OUTPUT TRISTATE ;
    USE SIGNAL ;
    PORT
      LAYER met2 ;
        RECT 234.690 0.000 234.970 4.000 ;
    END
  END X_imag[80]
  PIN X_imag[81]
    DIRECTION OUTPUT TRISTATE ;
    USE SIGNAL ;
    PORT
      LAYER met3 ;
        RECT 0.000 564.440 4.000 565.040 ;
    END
  END X_imag[81]
  PIN X_imag[82]
    DIRECTION OUTPUT TRISTATE ;
    USE SIGNAL ;
    PORT
      LAYER met3 ;
        RECT 0.000 479.440 4.000 480.040 ;
    END
  END X_imag[82]
  PIN X_imag[83]
    DIRECTION OUTPUT TRISTATE ;
    USE SIGNAL ;
    PORT
      LAYER met3 ;
        RECT 667.705 30.640 671.705 31.240 ;
    END
  END X_imag[83]
  PIN X_imag[84]
    DIRECTION OUTPUT TRISTATE ;
    USE SIGNAL ;
    PORT
      LAYER met2 ;
        RECT 593.490 678.425 593.770 682.425 ;
    END
  END X_imag[84]
  PIN X_imag[85]
    DIRECTION OUTPUT TRISTATE ;
    USE SIGNAL ;
    PORT
      LAYER met2 ;
        RECT 554.390 678.425 554.670 682.425 ;
    END
  END X_imag[85]
  PIN X_imag[86]
    DIRECTION OUTPUT TRISTATE ;
    USE SIGNAL ;
    PORT
      LAYER met3 ;
        RECT 667.705 265.240 671.705 265.840 ;
    END
  END X_imag[86]
  PIN X_imag[87]
    DIRECTION OUTPUT TRISTATE ;
    USE SIGNAL ;
    PORT
      LAYER met3 ;
        RECT 667.705 333.240 671.705 333.840 ;
    END
  END X_imag[87]
  PIN X_imag[88]
    DIRECTION OUTPUT TRISTATE ;
    USE SIGNAL ;
    PORT
      LAYER met2 ;
        RECT 147.290 678.425 147.570 682.425 ;
    END
  END X_imag[88]
  PIN X_imag[89]
    DIRECTION OUTPUT TRISTATE ;
    USE SIGNAL ;
    PORT
      LAYER met2 ;
        RECT 227.790 0.000 228.070 4.000 ;
    END
  END X_imag[89]
  PIN X_imag[8]
    DIRECTION OUTPUT TRISTATE ;
    USE SIGNAL ;
    PORT
      LAYER met2 ;
        RECT 460.090 0.000 460.370 4.000 ;
    END
  END X_imag[8]
  PIN X_imag[90]
    DIRECTION OUTPUT TRISTATE ;
    USE SIGNAL ;
    PORT
      LAYER met2 ;
        RECT 432.490 0.000 432.770 4.000 ;
    END
  END X_imag[90]
  PIN X_imag[91]
    DIRECTION OUTPUT TRISTATE ;
    USE SIGNAL ;
    PORT
      LAYER met3 ;
        RECT 667.705 557.640 671.705 558.240 ;
    END
  END X_imag[91]
  PIN X_imag[92]
    DIRECTION OUTPUT TRISTATE ;
    USE SIGNAL ;
    PORT
      LAYER met2 ;
        RECT 377.290 678.425 377.570 682.425 ;
    END
  END X_imag[92]
  PIN X_imag[93]
    DIRECTION OUTPUT TRISTATE ;
    USE SIGNAL ;
    PORT
      LAYER met2 ;
        RECT 87.490 0.000 87.770 4.000 ;
    END
  END X_imag[93]
  PIN X_imag[94]
    DIRECTION OUTPUT TRISTATE ;
    USE SIGNAL ;
    PORT
      LAYER met3 ;
        RECT 0.000 166.640 4.000 167.240 ;
    END
  END X_imag[94]
  PIN X_imag[95]
    DIRECTION OUTPUT TRISTATE ;
    USE SIGNAL ;
    PORT
      LAYER met3 ;
        RECT 0.000 360.440 4.000 361.040 ;
    END
  END X_imag[95]
  PIN X_imag[96]
    DIRECTION OUTPUT TRISTATE ;
    USE SIGNAL ;
    PORT
      LAYER met2 ;
        RECT 381.890 678.425 382.170 682.425 ;
    END
  END X_imag[96]
  PIN X_imag[97]
    DIRECTION OUTPUT TRISTATE ;
    USE SIGNAL ;
    PORT
      LAYER met2 ;
        RECT 149.590 0.000 149.870 4.000 ;
    END
  END X_imag[97]
  PIN X_imag[98]
    DIRECTION OUTPUT TRISTATE ;
    USE SIGNAL ;
    PORT
      LAYER met3 ;
        RECT 0.000 159.840 4.000 160.440 ;
    END
  END X_imag[98]
  PIN X_imag[99]
    DIRECTION OUTPUT TRISTATE ;
    USE SIGNAL ;
    PORT
      LAYER met2 ;
        RECT 522.190 0.000 522.470 4.000 ;
    END
  END X_imag[99]
  PIN X_imag[9]
    DIRECTION OUTPUT TRISTATE ;
    USE SIGNAL ;
    PORT
      LAYER met2 ;
        RECT 59.890 678.425 60.170 682.425 ;
    END
  END X_imag[9]
  PIN X_real[0]
    DIRECTION OUTPUT TRISTATE ;
    USE SIGNAL ;
    PORT
      LAYER met3 ;
        RECT 667.705 418.240 671.705 418.840 ;
    END
  END X_real[0]
  PIN X_real[100]
    DIRECTION OUTPUT TRISTATE ;
    USE SIGNAL ;
    PORT
      LAYER met3 ;
        RECT 0.000 438.640 4.000 439.240 ;
    END
  END X_real[100]
  PIN X_real[101]
    DIRECTION OUTPUT TRISTATE ;
    USE SIGNAL ;
    PORT
      LAYER met3 ;
        RECT 0.000 615.440 4.000 616.040 ;
    END
  END X_real[101]
  PIN X_real[102]
    DIRECTION OUTPUT TRISTATE ;
    USE SIGNAL ;
    PORT
      LAYER met3 ;
        RECT 667.705 132.640 671.705 133.240 ;
    END
  END X_real[102]
  PIN X_real[103]
    DIRECTION OUTPUT TRISTATE ;
    USE SIGNAL ;
    PORT
      LAYER met2 ;
        RECT 299.090 678.425 299.370 682.425 ;
    END
  END X_real[103]
  PIN X_real[104]
    DIRECTION OUTPUT TRISTATE ;
    USE SIGNAL ;
    PORT
      LAYER met2 ;
        RECT 478.490 0.000 478.770 4.000 ;
    END
  END X_real[104]
  PIN X_real[105]
    DIRECTION OUTPUT TRISTATE ;
    USE SIGNAL ;
    PORT
      LAYER met3 ;
        RECT 0.000 669.840 4.000 670.440 ;
    END
  END X_real[105]
  PIN X_real[106]
    DIRECTION OUTPUT TRISTATE ;
    USE SIGNAL ;
    PORT
      LAYER met2 ;
        RECT 443.990 0.000 444.270 4.000 ;
    END
  END X_real[106]
  PIN X_real[107]
    DIRECTION OUTPUT TRISTATE ;
    USE SIGNAL ;
    PORT
      LAYER met3 ;
        RECT 0.000 197.240 4.000 197.840 ;
    END
  END X_real[107]
  PIN X_real[108]
    DIRECTION OUTPUT TRISTATE ;
    USE SIGNAL ;
    PORT
      LAYER met2 ;
        RECT 124.290 0.000 124.570 4.000 ;
    END
  END X_real[108]
  PIN X_real[109]
    DIRECTION OUTPUT TRISTATE ;
    USE SIGNAL ;
    PORT
      LAYER met2 ;
        RECT 89.790 678.425 90.070 682.425 ;
    END
  END X_real[109]
  PIN X_real[10]
    DIRECTION OUTPUT TRISTATE ;
    USE SIGNAL ;
    PORT
      LAYER met2 ;
        RECT 273.790 678.425 274.070 682.425 ;
    END
  END X_real[10]
  PIN X_real[110]
    DIRECTION OUTPUT TRISTATE ;
    USE SIGNAL ;
    PORT
      LAYER met2 ;
        RECT 531.390 0.000 531.670 4.000 ;
    END
  END X_real[110]
  PIN X_real[111]
    DIRECTION OUTPUT TRISTATE ;
    USE SIGNAL ;
    PORT
      LAYER met2 ;
        RECT 71.390 0.000 71.670 4.000 ;
    END
  END X_real[111]
  PIN X_real[112]
    DIRECTION OUTPUT TRISTATE ;
    USE SIGNAL ;
    PORT
      LAYER met2 ;
        RECT 278.390 678.425 278.670 682.425 ;
    END
  END X_real[112]
  PIN X_real[113]
    DIRECTION OUTPUT TRISTATE ;
    USE SIGNAL ;
    PORT
      LAYER met3 ;
        RECT 667.705 649.440 671.705 650.040 ;
    END
  END X_real[113]
  PIN X_real[114]
    DIRECTION OUTPUT TRISTATE ;
    USE SIGNAL ;
    PORT
      LAYER met2 ;
        RECT 524.490 678.425 524.770 682.425 ;
    END
  END X_real[114]
  PIN X_real[115]
    DIRECTION OUTPUT TRISTATE ;
    USE SIGNAL ;
    PORT
      LAYER met2 ;
        RECT 591.190 678.425 591.470 682.425 ;
    END
  END X_real[115]
  PIN X_real[116]
    DIRECTION OUTPUT TRISTATE ;
    USE SIGNAL ;
    PORT
      LAYER met3 ;
        RECT 0.000 445.440 4.000 446.040 ;
    END
  END X_real[116]
  PIN X_real[117]
    DIRECTION OUTPUT TRISTATE ;
    USE SIGNAL ;
    PORT
      LAYER met2 ;
        RECT 209.390 678.425 209.670 682.425 ;
    END
  END X_real[117]
  PIN X_real[118]
    DIRECTION OUTPUT TRISTATE ;
    USE SIGNAL ;
    PORT
      LAYER met2 ;
        RECT 193.290 0.000 193.570 4.000 ;
    END
  END X_real[118]
  PIN X_real[119]
    DIRECTION OUTPUT TRISTATE ;
    USE SIGNAL ;
    PORT
      LAYER met3 ;
        RECT 0.000 183.640 4.000 184.240 ;
    END
  END X_real[119]
  PIN X_real[11]
    DIRECTION OUTPUT TRISTATE ;
    USE SIGNAL ;
    PORT
      LAYER met3 ;
        RECT 667.705 503.240 671.705 503.840 ;
    END
  END X_real[11]
  PIN X_real[120]
    DIRECTION OUTPUT TRISTATE ;
    USE SIGNAL ;
    PORT
      LAYER met2 ;
        RECT 572.790 678.425 573.070 682.425 ;
    END
  END X_real[120]
  PIN X_real[121]
    DIRECTION OUTPUT TRISTATE ;
    USE SIGNAL ;
    PORT
      LAYER met3 ;
        RECT 0.000 676.640 4.000 677.240 ;
    END
  END X_real[121]
  PIN X_real[122]
    DIRECTION OUTPUT TRISTATE ;
    USE SIGNAL ;
    PORT
      LAYER met3 ;
        RECT 0.000 595.040 4.000 595.640 ;
    END
  END X_real[122]
  PIN X_real[123]
    DIRECTION OUTPUT TRISTATE ;
    USE SIGNAL ;
    PORT
      LAYER met3 ;
        RECT 0.000 27.240 4.000 27.840 ;
    END
  END X_real[123]
  PIN X_real[124]
    DIRECTION OUTPUT TRISTATE ;
    USE SIGNAL ;
    PORT
      LAYER met2 ;
        RECT 402.590 0.000 402.870 4.000 ;
    END
  END X_real[124]
  PIN X_real[125]
    DIRECTION OUTPUT TRISTATE ;
    USE SIGNAL ;
    PORT
      LAYER met2 ;
        RECT 57.590 678.425 57.870 682.425 ;
    END
  END X_real[125]
  PIN X_real[126]
    DIRECTION OUTPUT TRISTATE ;
    USE SIGNAL ;
    PORT
      LAYER met2 ;
        RECT 441.690 678.425 441.970 682.425 ;
    END
  END X_real[126]
  PIN X_real[127]
    DIRECTION OUTPUT TRISTATE ;
    USE SIGNAL ;
    PORT
      LAYER met2 ;
        RECT 506.090 0.000 506.370 4.000 ;
    END
  END X_real[127]
  PIN X_real[128]
    DIRECTION OUTPUT TRISTATE ;
    USE SIGNAL ;
    PORT
      LAYER met2 ;
        RECT 197.890 0.000 198.170 4.000 ;
    END
  END X_real[128]
  PIN X_real[129]
    DIRECTION OUTPUT TRISTATE ;
    USE SIGNAL ;
    PORT
      LAYER met2 ;
        RECT 94.390 678.425 94.670 682.425 ;
    END
  END X_real[129]
  PIN X_real[12]
    DIRECTION OUTPUT TRISTATE ;
    USE SIGNAL ;
    PORT
      LAYER met3 ;
        RECT 0.000 561.040 4.000 561.640 ;
    END
  END X_real[12]
  PIN X_real[130]
    DIRECTION OUTPUT TRISTATE ;
    USE SIGNAL ;
    PORT
      LAYER met2 ;
        RECT 248.490 678.425 248.770 682.425 ;
    END
  END X_real[130]
  PIN X_real[131]
    DIRECTION OUTPUT TRISTATE ;
    USE SIGNAL ;
    PORT
      LAYER met3 ;
        RECT 0.000 214.240 4.000 214.840 ;
    END
  END X_real[131]
  PIN X_real[132]
    DIRECTION OUTPUT TRISTATE ;
    USE SIGNAL ;
    PORT
      LAYER met3 ;
        RECT 667.705 54.440 671.705 55.040 ;
    END
  END X_real[132]
  PIN X_real[133]
    DIRECTION OUTPUT TRISTATE ;
    USE SIGNAL ;
    PORT
      LAYER met2 ;
        RECT 660.190 678.425 660.470 682.425 ;
    END
  END X_real[133]
  PIN X_real[134]
    DIRECTION OUTPUT TRISTATE ;
    USE SIGNAL ;
    PORT
      LAYER met2 ;
        RECT 239.290 0.000 239.570 4.000 ;
    END
  END X_real[134]
  PIN X_real[135]
    DIRECTION OUTPUT TRISTATE ;
    USE SIGNAL ;
    PORT
      LAYER met3 ;
        RECT 667.705 173.440 671.705 174.040 ;
    END
  END X_real[135]
  PIN X_real[136]
    DIRECTION OUTPUT TRISTATE ;
    USE SIGNAL ;
    PORT
      LAYER met2 ;
        RECT 98.990 0.000 99.270 4.000 ;
    END
  END X_real[136]
  PIN X_real[137]
    DIRECTION OUTPUT TRISTATE ;
    USE SIGNAL ;
    PORT
      LAYER met3 ;
        RECT 0.000 153.040 4.000 153.640 ;
    END
  END X_real[137]
  PIN X_real[138]
    DIRECTION OUTPUT TRISTATE ;
    USE SIGNAL ;
    PORT
      LAYER met3 ;
        RECT 0.000 384.240 4.000 384.840 ;
    END
  END X_real[138]
  PIN X_real[139]
    DIRECTION OUTPUT TRISTATE ;
    USE SIGNAL ;
    PORT
      LAYER met3 ;
        RECT 667.705 442.040 671.705 442.640 ;
    END
  END X_real[139]
  PIN X_real[13]
    DIRECTION OUTPUT TRISTATE ;
    USE SIGNAL ;
    PORT
      LAYER met2 ;
        RECT 213.990 0.000 214.270 4.000 ;
    END
  END X_real[13]
  PIN X_real[140]
    DIRECTION OUTPUT TRISTATE ;
    USE SIGNAL ;
    PORT
      LAYER met2 ;
        RECT 305.990 0.000 306.270 4.000 ;
    END
  END X_real[140]
  PIN X_real[141]
    DIRECTION OUTPUT TRISTATE ;
    USE SIGNAL ;
    PORT
      LAYER met3 ;
        RECT 667.705 404.640 671.705 405.240 ;
    END
  END X_real[141]
  PIN X_real[142]
    DIRECTION OUTPUT TRISTATE ;
    USE SIGNAL ;
    PORT
      LAYER met2 ;
        RECT 393.390 678.425 393.670 682.425 ;
    END
  END X_real[142]
  PIN X_real[143]
    DIRECTION OUTPUT TRISTATE ;
    USE SIGNAL ;
    PORT
      LAYER met2 ;
        RECT 131.190 678.425 131.470 682.425 ;
    END
  END X_real[143]
  PIN X_real[144]
    DIRECTION OUTPUT TRISTATE ;
    USE SIGNAL ;
    PORT
      LAYER met3 ;
        RECT 0.000 13.640 4.000 14.240 ;
    END
  END X_real[144]
  PIN X_real[145]
    DIRECTION OUTPUT TRISTATE ;
    USE SIGNAL ;
    PORT
      LAYER met2 ;
        RECT 411.790 0.000 412.070 4.000 ;
    END
  END X_real[145]
  PIN X_real[146]
    DIRECTION OUTPUT TRISTATE ;
    USE SIGNAL ;
    PORT
      LAYER met3 ;
        RECT 0.000 646.040 4.000 646.640 ;
    END
  END X_real[146]
  PIN X_real[147]
    DIRECTION OUTPUT TRISTATE ;
    USE SIGNAL ;
    PORT
      LAYER met2 ;
        RECT 386.490 0.000 386.770 4.000 ;
    END
  END X_real[147]
  PIN X_real[148]
    DIRECTION OUTPUT TRISTATE ;
    USE SIGNAL ;
    PORT
      LAYER met3 ;
        RECT 667.705 272.040 671.705 272.640 ;
    END
  END X_real[148]
  PIN X_real[149]
    DIRECTION OUTPUT TRISTATE ;
    USE SIGNAL ;
    PORT
      LAYER met2 ;
        RECT 535.990 0.000 536.270 4.000 ;
    END
  END X_real[149]
  PIN X_real[14]
    DIRECTION OUTPUT TRISTATE ;
    USE SIGNAL ;
    PORT
      LAYER met2 ;
        RECT 289.890 678.425 290.170 682.425 ;
    END
  END X_real[14]
  PIN X_real[150]
    DIRECTION OUTPUT TRISTATE ;
    USE SIGNAL ;
    PORT
      LAYER met3 ;
        RECT 667.705 394.440 671.705 395.040 ;
    END
  END X_real[150]
  PIN X_real[151]
    DIRECTION OUTPUT TRISTATE ;
    USE SIGNAL ;
    PORT
      LAYER met2 ;
        RECT 347.390 678.425 347.670 682.425 ;
    END
  END X_real[151]
  PIN X_real[152]
    DIRECTION OUTPUT TRISTATE ;
    USE SIGNAL ;
    PORT
      LAYER met3 ;
        RECT 667.705 380.840 671.705 381.440 ;
    END
  END X_real[152]
  PIN X_real[153]
    DIRECTION OUTPUT TRISTATE ;
    USE SIGNAL ;
    PORT
      LAYER met2 ;
        RECT 598.090 678.425 598.370 682.425 ;
    END
  END X_real[153]
  PIN X_real[154]
    DIRECTION OUTPUT TRISTATE ;
    USE SIGNAL ;
    PORT
      LAYER met2 ;
        RECT 648.690 678.425 648.970 682.425 ;
    END
  END X_real[154]
  PIN X_real[155]
    DIRECTION OUTPUT TRISTATE ;
    USE SIGNAL ;
    PORT
      LAYER met2 ;
        RECT 391.090 0.000 391.370 4.000 ;
    END
  END X_real[155]
  PIN X_real[156]
    DIRECTION OUTPUT TRISTATE ;
    USE SIGNAL ;
    PORT
      LAYER met2 ;
        RECT 450.890 678.425 451.170 682.425 ;
    END
  END X_real[156]
  PIN X_real[157]
    DIRECTION OUTPUT TRISTATE ;
    USE SIGNAL ;
    PORT
      LAYER met3 ;
        RECT 0.000 142.840 4.000 143.440 ;
    END
  END X_real[157]
  PIN X_real[158]
    DIRECTION OUTPUT TRISTATE ;
    USE SIGNAL ;
    PORT
      LAYER met2 ;
        RECT 653.290 0.000 653.570 4.000 ;
    END
  END X_real[158]
  PIN X_real[159]
    DIRECTION OUTPUT TRISTATE ;
    USE SIGNAL ;
    PORT
      LAYER met3 ;
        RECT 667.705 374.040 671.705 374.640 ;
    END
  END X_real[159]
  PIN X_real[15]
    DIRECTION OUTPUT TRISTATE ;
    USE SIGNAL ;
    PORT
      LAYER met2 ;
        RECT 354.290 0.000 354.570 4.000 ;
    END
  END X_real[15]
  PIN X_real[160]
    DIRECTION OUTPUT TRISTATE ;
    USE SIGNAL ;
    PORT
      LAYER met3 ;
        RECT 0.000 306.040 4.000 306.640 ;
    END
  END X_real[160]
  PIN X_real[161]
    DIRECTION OUTPUT TRISTATE ;
    USE SIGNAL ;
    PORT
      LAYER met2 ;
        RECT 36.890 678.425 37.170 682.425 ;
    END
  END X_real[161]
  PIN X_real[162]
    DIRECTION OUTPUT TRISTATE ;
    USE SIGNAL ;
    PORT
      LAYER met2 ;
        RECT 312.890 0.000 313.170 4.000 ;
    END
  END X_real[162]
  PIN X_real[163]
    DIRECTION OUTPUT TRISTATE ;
    USE SIGNAL ;
    PORT
      LAYER met3 ;
        RECT 667.705 489.640 671.705 490.240 ;
    END
  END X_real[163]
  PIN X_real[164]
    DIRECTION OUTPUT TRISTATE ;
    USE SIGNAL ;
    PORT
      LAYER met3 ;
        RECT 667.705 635.840 671.705 636.440 ;
    END
  END X_real[164]
  PIN X_real[165]
    DIRECTION OUTPUT TRISTATE ;
    USE SIGNAL ;
    PORT
      LAYER met3 ;
        RECT 0.000 81.640 4.000 82.240 ;
    END
  END X_real[165]
  PIN X_real[166]
    DIRECTION OUTPUT TRISTATE ;
    USE SIGNAL ;
    PORT
      LAYER met3 ;
        RECT 667.705 482.840 671.705 483.440 ;
    END
  END X_real[166]
  PIN X_real[167]
    DIRECTION OUTPUT TRISTATE ;
    USE SIGNAL ;
    PORT
      LAYER met2 ;
        RECT 296.790 0.000 297.070 4.000 ;
    END
  END X_real[167]
  PIN X_real[168]
    DIRECTION OUTPUT TRISTATE ;
    USE SIGNAL ;
    PORT
      LAYER met2 ;
        RECT 163.390 678.425 163.670 682.425 ;
    END
  END X_real[168]
  PIN X_real[169]
    DIRECTION OUTPUT TRISTATE ;
    USE SIGNAL ;
    PORT
      LAYER met3 ;
        RECT 0.000 625.640 4.000 626.240 ;
    END
  END X_real[169]
  PIN X_real[16]
    DIRECTION OUTPUT TRISTATE ;
    USE SIGNAL ;
    PORT
      LAYER met3 ;
        RECT 667.705 163.240 671.705 163.840 ;
    END
  END X_real[16]
  PIN X_real[170]
    DIRECTION OUTPUT TRISTATE ;
    USE SIGNAL ;
    PORT
      LAYER met3 ;
        RECT 667.705 139.440 671.705 140.040 ;
    END
  END X_real[170]
  PIN X_real[171]
    DIRECTION OUTPUT TRISTATE ;
    USE SIGNAL ;
    PORT
      LAYER met3 ;
        RECT 667.705 513.440 671.705 514.040 ;
    END
  END X_real[171]
  PIN X_real[172]
    DIRECTION OUTPUT TRISTATE ;
    USE SIGNAL ;
    PORT
      LAYER met3 ;
        RECT 0.000 506.640 4.000 507.240 ;
    END
  END X_real[172]
  PIN X_real[173]
    DIRECTION OUTPUT TRISTATE ;
    USE SIGNAL ;
    PORT
      LAYER met3 ;
        RECT 667.705 397.840 671.705 398.440 ;
    END
  END X_real[173]
  PIN X_real[174]
    DIRECTION OUTPUT TRISTATE ;
    USE SIGNAL ;
    PORT
      LAYER met3 ;
        RECT 667.705 326.440 671.705 327.040 ;
    END
  END X_real[174]
  PIN X_real[175]
    DIRECTION OUTPUT TRISTATE ;
    USE SIGNAL ;
    PORT
      LAYER met2 ;
        RECT 641.790 0.000 642.070 4.000 ;
    END
  END X_real[175]
  PIN X_real[176]
    DIRECTION OUTPUT TRISTATE ;
    USE SIGNAL ;
    PORT
      LAYER met3 ;
        RECT 667.705 193.840 671.705 194.440 ;
    END
  END X_real[176]
  PIN X_real[177]
    DIRECTION OUTPUT TRISTATE ;
    USE SIGNAL ;
    PORT
      LAYER met3 ;
        RECT 667.705 387.640 671.705 388.240 ;
    END
  END X_real[177]
  PIN X_real[178]
    DIRECTION OUTPUT TRISTATE ;
    USE SIGNAL ;
    PORT
      LAYER met2 ;
        RECT 591.190 0.000 591.470 4.000 ;
    END
  END X_real[178]
  PIN X_real[179]
    DIRECTION OUTPUT TRISTATE ;
    USE SIGNAL ;
    PORT
      LAYER met2 ;
        RECT 308.290 0.000 308.570 4.000 ;
    END
  END X_real[179]
  PIN X_real[17]
    DIRECTION OUTPUT TRISTATE ;
    USE SIGNAL ;
    PORT
      LAYER met2 ;
        RECT 400.290 678.425 400.570 682.425 ;
    END
  END X_real[17]
  PIN X_real[180]
    DIRECTION OUTPUT TRISTATE ;
    USE SIGNAL ;
    PORT
      LAYER met3 ;
        RECT 0.000 649.440 4.000 650.040 ;
    END
  END X_real[180]
  PIN X_real[181]
    DIRECTION OUTPUT TRISTATE ;
    USE SIGNAL ;
    PORT
      LAYER met2 ;
        RECT 503.790 678.425 504.070 682.425 ;
    END
  END X_real[181]
  PIN X_real[182]
    DIRECTION OUTPUT TRISTATE ;
    USE SIGNAL ;
    PORT
      LAYER met2 ;
        RECT 508.390 678.425 508.670 682.425 ;
    END
  END X_real[182]
  PIN X_real[183]
    DIRECTION OUTPUT TRISTATE ;
    USE SIGNAL ;
    PORT
      LAYER met2 ;
        RECT 423.290 0.000 423.570 4.000 ;
    END
  END X_real[183]
  PIN X_real[184]
    DIRECTION OUTPUT TRISTATE ;
    USE SIGNAL ;
    PORT
      LAYER met2 ;
        RECT 243.890 0.000 244.170 4.000 ;
    END
  END X_real[184]
  PIN X_real[185]
    DIRECTION OUTPUT TRISTATE ;
    USE SIGNAL ;
    PORT
      LAYER met3 ;
        RECT 0.000 639.240 4.000 639.840 ;
    END
  END X_real[185]
  PIN X_real[186]
    DIRECTION OUTPUT TRISTATE ;
    USE SIGNAL ;
    PORT
      LAYER met3 ;
        RECT 0.000 323.040 4.000 323.640 ;
    END
  END X_real[186]
  PIN X_real[187]
    DIRECTION OUTPUT TRISTATE ;
    USE SIGNAL ;
    PORT
      LAYER met2 ;
        RECT 305.990 678.425 306.270 682.425 ;
    END
  END X_real[187]
  PIN X_real[188]
    DIRECTION OUTPUT TRISTATE ;
    USE SIGNAL ;
    PORT
      LAYER met3 ;
        RECT 667.705 496.440 671.705 497.040 ;
    END
  END X_real[188]
  PIN X_real[189]
    DIRECTION OUTPUT TRISTATE ;
    USE SIGNAL ;
    PORT
      LAYER met3 ;
        RECT 667.705 312.840 671.705 313.440 ;
    END
  END X_real[189]
  PIN X_real[18]
    DIRECTION OUTPUT TRISTATE ;
    USE SIGNAL ;
    PORT
      LAYER met2 ;
        RECT 140.390 0.000 140.670 4.000 ;
    END
  END X_real[18]
  PIN X_real[190]
    DIRECTION OUTPUT TRISTATE ;
    USE SIGNAL ;
    PORT
      LAYER met3 ;
        RECT 667.705 598.440 671.705 599.040 ;
    END
  END X_real[190]
  PIN X_real[191]
    DIRECTION OUTPUT TRISTATE ;
    USE SIGNAL ;
    PORT
      LAYER met2 ;
        RECT 324.390 0.000 324.670 4.000 ;
    END
  END X_real[191]
  PIN X_real[192]
    DIRECTION OUTPUT TRISTATE ;
    USE SIGNAL ;
    PORT
      LAYER met3 ;
        RECT 667.705 200.640 671.705 201.240 ;
    END
  END X_real[192]
  PIN X_real[193]
    DIRECTION OUTPUT TRISTATE ;
    USE SIGNAL ;
    PORT
      LAYER met3 ;
        RECT 667.705 241.440 671.705 242.040 ;
    END
  END X_real[193]
  PIN X_real[194]
    DIRECTION OUTPUT TRISTATE ;
    USE SIGNAL ;
    PORT
      LAYER met2 ;
        RECT 181.790 0.000 182.070 4.000 ;
    END
  END X_real[194]
  PIN X_real[195]
    DIRECTION OUTPUT TRISTATE ;
    USE SIGNAL ;
    PORT
      LAYER met2 ;
        RECT 142.690 678.425 142.970 682.425 ;
    END
  END X_real[195]
  PIN X_real[196]
    DIRECTION OUTPUT TRISTATE ;
    USE SIGNAL ;
    PORT
      LAYER met2 ;
        RECT 420.990 0.000 421.270 4.000 ;
    END
  END X_real[196]
  PIN X_real[197]
    DIRECTION OUTPUT TRISTATE ;
    USE SIGNAL ;
    PORT
      LAYER met3 ;
        RECT 667.705 295.840 671.705 296.440 ;
    END
  END X_real[197]
  PIN X_real[198]
    DIRECTION OUTPUT TRISTATE ;
    USE SIGNAL ;
    PORT
      LAYER met3 ;
        RECT 0.000 136.040 4.000 136.640 ;
    END
  END X_real[198]
  PIN X_real[199]
    DIRECTION OUTPUT TRISTATE ;
    USE SIGNAL ;
    PORT
      LAYER met2 ;
        RECT 250.790 0.000 251.070 4.000 ;
    END
  END X_real[199]
  PIN X_real[19]
    DIRECTION OUTPUT TRISTATE ;
    USE SIGNAL ;
    PORT
      LAYER met3 ;
        RECT 0.000 584.840 4.000 585.440 ;
    END
  END X_real[19]
  PIN X_real[1]
    DIRECTION OUTPUT TRISTATE ;
    USE SIGNAL ;
    PORT
      LAYER met2 ;
        RECT 374.990 0.000 375.270 4.000 ;
    END
  END X_real[1]
  PIN X_real[200]
    DIRECTION OUTPUT TRISTATE ;
    USE SIGNAL ;
    PORT
      LAYER met2 ;
        RECT 483.090 678.425 483.370 682.425 ;
    END
  END X_real[200]
  PIN X_real[201]
    DIRECTION OUTPUT TRISTATE ;
    USE SIGNAL ;
    PORT
      LAYER met2 ;
        RECT 409.490 678.425 409.770 682.425 ;
    END
  END X_real[201]
  PIN X_real[202]
    DIRECTION OUTPUT TRISTATE ;
    USE SIGNAL ;
    PORT
      LAYER met2 ;
        RECT 135.790 0.000 136.070 4.000 ;
    END
  END X_real[202]
  PIN X_real[203]
    DIRECTION OUTPUT TRISTATE ;
    USE SIGNAL ;
    PORT
      LAYER met2 ;
        RECT 637.190 0.000 637.470 4.000 ;
    END
  END X_real[203]
  PIN X_real[204]
    DIRECTION OUTPUT TRISTATE ;
    USE SIGNAL ;
    PORT
      LAYER met2 ;
        RECT 577.390 678.425 577.670 682.425 ;
    END
  END X_real[204]
  PIN X_real[205]
    DIRECTION OUTPUT TRISTATE ;
    USE SIGNAL ;
    PORT
      LAYER met3 ;
        RECT 0.000 510.040 4.000 510.640 ;
    END
  END X_real[205]
  PIN X_real[206]
    DIRECTION OUTPUT TRISTATE ;
    USE SIGNAL ;
    PORT
      LAYER met2 ;
        RECT 370.390 0.000 370.670 4.000 ;
    END
  END X_real[206]
  PIN X_real[207]
    DIRECTION OUTPUT TRISTATE ;
    USE SIGNAL ;
    PORT
      LAYER met2 ;
        RECT 535.990 678.425 536.270 682.425 ;
    END
  END X_real[207]
  PIN X_real[208]
    DIRECTION OUTPUT TRISTATE ;
    USE SIGNAL ;
    PORT
      LAYER met2 ;
        RECT 667.090 678.425 667.370 682.425 ;
    END
  END X_real[208]
  PIN X_real[209]
    DIRECTION OUTPUT TRISTATE ;
    USE SIGNAL ;
    PORT
      LAYER met2 ;
        RECT 480.790 0.000 481.070 4.000 ;
    END
  END X_real[209]
  PIN X_real[20]
    DIRECTION OUTPUT TRISTATE ;
    USE SIGNAL ;
    PORT
      LAYER met2 ;
        RECT 85.190 678.425 85.470 682.425 ;
    END
  END X_real[20]
  PIN X_real[210]
    DIRECTION OUTPUT TRISTATE ;
    USE SIGNAL ;
    PORT
      LAYER met2 ;
        RECT 177.190 0.000 177.470 4.000 ;
    END
  END X_real[210]
  PIN X_real[211]
    DIRECTION OUTPUT TRISTATE ;
    USE SIGNAL ;
    PORT
      LAYER met3 ;
        RECT 0.000 227.840 4.000 228.440 ;
    END
  END X_real[211]
  PIN X_real[212]
    DIRECTION OUTPUT TRISTATE ;
    USE SIGNAL ;
    PORT
      LAYER met2 ;
        RECT 128.890 0.000 129.170 4.000 ;
    END
  END X_real[212]
  PIN X_real[213]
    DIRECTION OUTPUT TRISTATE ;
    USE SIGNAL ;
    PORT
      LAYER met2 ;
        RECT 457.790 0.000 458.070 4.000 ;
    END
  END X_real[213]
  PIN X_real[214]
    DIRECTION OUTPUT TRISTATE ;
    USE SIGNAL ;
    PORT
      LAYER met3 ;
        RECT 0.000 57.840 4.000 58.440 ;
    END
  END X_real[214]
  PIN X_real[215]
    DIRECTION OUTPUT TRISTATE ;
    USE SIGNAL ;
    PORT
      LAYER met3 ;
        RECT 667.705 459.040 671.705 459.640 ;
    END
  END X_real[215]
  PIN X_real[216]
    DIRECTION OUTPUT TRISTATE ;
    USE SIGNAL ;
    PORT
      LAYER met2 ;
        RECT 667.090 0.000 667.370 4.000 ;
    END
  END X_real[216]
  PIN X_real[217]
    DIRECTION OUTPUT TRISTATE ;
    USE SIGNAL ;
    PORT
      LAYER met3 ;
        RECT 0.000 251.640 4.000 252.240 ;
    END
  END X_real[217]
  PIN X_real[218]
    DIRECTION OUTPUT TRISTATE ;
    USE SIGNAL ;
    PORT
      LAYER met2 ;
        RECT 345.090 0.000 345.370 4.000 ;
    END
  END X_real[218]
  PIN X_real[219]
    DIRECTION OUTPUT TRISTATE ;
    USE SIGNAL ;
    PORT
      LAYER met3 ;
        RECT 0.000 414.840 4.000 415.440 ;
    END
  END X_real[219]
  PIN X_real[21]
    DIRECTION OUTPUT TRISTATE ;
    USE SIGNAL ;
    PORT
      LAYER met2 ;
        RECT 294.490 678.425 294.770 682.425 ;
    END
  END X_real[21]
  PIN X_real[220]
    DIRECTION OUTPUT TRISTATE ;
    USE SIGNAL ;
    PORT
      LAYER met2 ;
        RECT 179.490 678.425 179.770 682.425 ;
    END
  END X_real[220]
  PIN X_real[221]
    DIRECTION OUTPUT TRISTATE ;
    USE SIGNAL ;
    PORT
      LAYER met2 ;
        RECT 50.690 0.000 50.970 4.000 ;
    END
  END X_real[221]
  PIN X_real[222]
    DIRECTION OUTPUT TRISTATE ;
    USE SIGNAL ;
    PORT
      LAYER met2 ;
        RECT 533.690 678.425 533.970 682.425 ;
    END
  END X_real[222]
  PIN X_real[223]
    DIRECTION OUTPUT TRISTATE ;
    USE SIGNAL ;
    PORT
      LAYER met3 ;
        RECT 0.000 622.240 4.000 622.840 ;
    END
  END X_real[223]
  PIN X_real[224]
    DIRECTION OUTPUT TRISTATE ;
    USE SIGNAL ;
    PORT
      LAYER met2 ;
        RECT 165.690 0.000 165.970 4.000 ;
    END
  END X_real[224]
  PIN X_real[225]
    DIRECTION OUTPUT TRISTATE ;
    USE SIGNAL ;
    PORT
      LAYER met3 ;
        RECT 667.705 642.640 671.705 643.240 ;
    END
  END X_real[225]
  PIN X_real[226]
    DIRECTION OUTPUT TRISTATE ;
    USE SIGNAL ;
    PORT
      LAYER met3 ;
        RECT 667.705 125.840 671.705 126.440 ;
    END
  END X_real[226]
  PIN X_real[227]
    DIRECTION OUTPUT TRISTATE ;
    USE SIGNAL ;
    PORT
      LAYER met2 ;
        RECT 662.490 0.000 662.770 4.000 ;
    END
  END X_real[227]
  PIN X_real[228]
    DIRECTION OUTPUT TRISTATE ;
    USE SIGNAL ;
    PORT
      LAYER met3 ;
        RECT 0.000 663.040 4.000 663.640 ;
    END
  END X_real[228]
  PIN X_real[229]
    DIRECTION OUTPUT TRISTATE ;
    USE SIGNAL ;
    PORT
      LAYER met2 ;
        RECT 581.990 678.425 582.270 682.425 ;
    END
  END X_real[229]
  PIN X_real[22]
    DIRECTION OUTPUT TRISTATE ;
    USE SIGNAL ;
    PORT
      LAYER met2 ;
        RECT 108.190 0.000 108.470 4.000 ;
    END
  END X_real[22]
  PIN X_real[230]
    DIRECTION OUTPUT TRISTATE ;
    USE SIGNAL ;
    PORT
      LAYER met3 ;
        RECT 0.000 537.240 4.000 537.840 ;
    END
  END X_real[230]
  PIN X_real[231]
    DIRECTION OUTPUT TRISTATE ;
    USE SIGNAL ;
    PORT
      LAYER met2 ;
        RECT 368.090 678.425 368.370 682.425 ;
    END
  END X_real[231]
  PIN X_real[232]
    DIRECTION OUTPUT TRISTATE ;
    USE SIGNAL ;
    PORT
      LAYER met2 ;
        RECT 64.490 678.425 64.770 682.425 ;
    END
  END X_real[232]
  PIN X_real[233]
    DIRECTION OUTPUT TRISTATE ;
    USE SIGNAL ;
    PORT
      LAYER met2 ;
        RECT 604.990 0.000 605.270 4.000 ;
    END
  END X_real[233]
  PIN X_real[234]
    DIRECTION OUTPUT TRISTATE ;
    USE SIGNAL ;
    PORT
      LAYER met2 ;
        RECT 427.890 0.000 428.170 4.000 ;
    END
  END X_real[234]
  PIN X_real[235]
    DIRECTION OUTPUT TRISTATE ;
    USE SIGNAL ;
    PORT
      LAYER met2 ;
        RECT 292.190 0.000 292.470 4.000 ;
    END
  END X_real[235]
  PIN X_real[236]
    DIRECTION OUTPUT TRISTATE ;
    USE SIGNAL ;
    PORT
      LAYER met2 ;
        RECT 154.190 678.425 154.470 682.425 ;
    END
  END X_real[236]
  PIN X_real[237]
    DIRECTION OUTPUT TRISTATE ;
    USE SIGNAL ;
    PORT
      LAYER met3 ;
        RECT 667.705 309.440 671.705 310.040 ;
    END
  END X_real[237]
  PIN X_real[238]
    DIRECTION OUTPUT TRISTATE ;
    USE SIGNAL ;
    PORT
      LAYER met3 ;
        RECT 0.000 20.440 4.000 21.040 ;
    END
  END X_real[238]
  PIN X_real[239]
    DIRECTION OUTPUT TRISTATE ;
    USE SIGNAL ;
    PORT
      LAYER met2 ;
        RECT 11.590 678.425 11.870 682.425 ;
    END
  END X_real[239]
  PIN X_real[23]
    DIRECTION OUTPUT TRISTATE ;
    USE SIGNAL ;
    PORT
      LAYER met2 ;
        RECT 266.890 678.425 267.170 682.425 ;
    END
  END X_real[23]
  PIN X_real[240]
    DIRECTION OUTPUT TRISTATE ;
    USE SIGNAL ;
    PORT
      LAYER met3 ;
        RECT 0.000 200.640 4.000 201.240 ;
    END
  END X_real[240]
  PIN X_real[241]
    DIRECTION OUTPUT TRISTATE ;
    USE SIGNAL ;
    PORT
      LAYER met3 ;
        RECT 0.000 268.640 4.000 269.240 ;
    END
  END X_real[241]
  PIN X_real[242]
    DIRECTION OUTPUT TRISTATE ;
    USE SIGNAL ;
    PORT
      LAYER met2 ;
        RECT 519.890 678.425 520.170 682.425 ;
    END
  END X_real[242]
  PIN X_real[243]
    DIRECTION OUTPUT TRISTATE ;
    USE SIGNAL ;
    PORT
      LAYER met2 ;
        RECT 303.690 678.425 303.970 682.425 ;
    END
  END X_real[243]
  PIN X_real[244]
    DIRECTION OUTPUT TRISTATE ;
    USE SIGNAL ;
    PORT
      LAYER met2 ;
        RECT 538.290 0.000 538.570 4.000 ;
    END
  END X_real[244]
  PIN X_real[245]
    DIRECTION OUTPUT TRISTATE ;
    USE SIGNAL ;
    PORT
      LAYER met3 ;
        RECT 0.000 608.640 4.000 609.240 ;
    END
  END X_real[245]
  PIN X_real[246]
    DIRECTION OUTPUT TRISTATE ;
    USE SIGNAL ;
    PORT
      LAYER met2 ;
        RECT 586.590 678.425 586.870 682.425 ;
    END
  END X_real[246]
  PIN X_real[247]
    DIRECTION OUTPUT TRISTATE ;
    USE SIGNAL ;
    PORT
      LAYER met3 ;
        RECT 0.000 452.240 4.000 452.840 ;
    END
  END X_real[247]
  PIN X_real[248]
    DIRECTION OUTPUT TRISTATE ;
    USE SIGNAL ;
    PORT
      LAYER met2 ;
        RECT 414.090 678.425 414.370 682.425 ;
    END
  END X_real[248]
  PIN X_real[249]
    DIRECTION OUTPUT TRISTATE ;
    USE SIGNAL ;
    PORT
      LAYER met2 ;
        RECT 600.390 0.000 600.670 4.000 ;
    END
  END X_real[249]
  PIN X_real[24]
    DIRECTION OUTPUT TRISTATE ;
    USE SIGNAL ;
    PORT
      LAYER met3 ;
        RECT 0.000 462.440 4.000 463.040 ;
    END
  END X_real[24]
  PIN X_real[250]
    DIRECTION OUTPUT TRISTATE ;
    USE SIGNAL ;
    PORT
      LAYER met2 ;
        RECT 269.190 678.425 269.470 682.425 ;
    END
  END X_real[250]
  PIN X_real[251]
    DIRECTION OUTPUT TRISTATE ;
    USE SIGNAL ;
    PORT
      LAYER met2 ;
        RECT 9.290 0.000 9.570 4.000 ;
    END
  END X_real[251]
  PIN X_real[252]
    DIRECTION OUTPUT TRISTATE ;
    USE SIGNAL ;
    PORT
      LAYER met2 ;
        RECT 29.990 0.000 30.270 4.000 ;
    END
  END X_real[252]
  PIN X_real[253]
    DIRECTION OUTPUT TRISTATE ;
    USE SIGNAL ;
    PORT
      LAYER met2 ;
        RECT 349.690 0.000 349.970 4.000 ;
    END
  END X_real[253]
  PIN X_real[254]
    DIRECTION OUTPUT TRISTATE ;
    USE SIGNAL ;
    PORT
      LAYER met2 ;
        RECT 561.290 678.425 561.570 682.425 ;
    END
  END X_real[254]
  PIN X_real[255]
    DIRECTION OUTPUT TRISTATE ;
    USE SIGNAL ;
    PORT
      LAYER met3 ;
        RECT 667.705 465.840 671.705 466.440 ;
    END
  END X_real[255]
  PIN X_real[25]
    DIRECTION OUTPUT TRISTATE ;
    USE SIGNAL ;
    PORT
      LAYER met3 ;
        RECT 667.705 343.440 671.705 344.040 ;
    END
  END X_real[25]
  PIN X_real[26]
    DIRECTION OUTPUT TRISTATE ;
    USE SIGNAL ;
    PORT
      LAYER met2 ;
        RECT 335.890 678.425 336.170 682.425 ;
    END
  END X_real[26]
  PIN X_real[27]
    DIRECTION OUTPUT TRISTATE ;
    USE SIGNAL ;
    PORT
      LAYER met3 ;
        RECT 667.705 435.240 671.705 435.840 ;
    END
  END X_real[27]
  PIN X_real[28]
    DIRECTION OUTPUT TRISTATE ;
    USE SIGNAL ;
    PORT
      LAYER met2 ;
        RECT 211.690 678.425 211.970 682.425 ;
    END
  END X_real[28]
  PIN X_real[29]
    DIRECTION OUTPUT TRISTATE ;
    USE SIGNAL ;
    PORT
      LAYER met3 ;
        RECT 0.000 30.640 4.000 31.240 ;
    END
  END X_real[29]
  PIN X_real[2]
    DIRECTION OUTPUT TRISTATE ;
    USE SIGNAL ;
    PORT
      LAYER met3 ;
        RECT 0.000 391.040 4.000 391.640 ;
    END
  END X_real[2]
  PIN X_real[30]
    DIRECTION OUTPUT TRISTATE ;
    USE SIGNAL ;
    PORT
      LAYER met2 ;
        RECT 345.090 678.425 345.370 682.425 ;
    END
  END X_real[30]
  PIN X_real[31]
    DIRECTION OUTPUT TRISTATE ;
    USE SIGNAL ;
    PORT
      LAYER met2 ;
        RECT 338.190 0.000 338.470 4.000 ;
    END
  END X_real[31]
  PIN X_real[32]
    DIRECTION OUTPUT TRISTATE ;
    USE SIGNAL ;
    PORT
      LAYER met2 ;
        RECT 282.990 678.425 283.270 682.425 ;
    END
  END X_real[32]
  PIN X_real[33]
    DIRECTION OUTPUT TRISTATE ;
    USE SIGNAL ;
    PORT
      LAYER met3 ;
        RECT 0.000 244.840 4.000 245.440 ;
    END
  END X_real[33]
  PIN X_real[34]
    DIRECTION OUTPUT TRISTATE ;
    USE SIGNAL ;
    PORT
      LAYER met2 ;
        RECT 62.190 0.000 62.470 4.000 ;
    END
  END X_real[34]
  PIN X_real[35]
    DIRECTION OUTPUT TRISTATE ;
    USE SIGNAL ;
    PORT
      LAYER met2 ;
        RECT 552.090 0.000 552.370 4.000 ;
    END
  END X_real[35]
  PIN X_real[36]
    DIRECTION OUTPUT TRISTATE ;
    USE SIGNAL ;
    PORT
      LAYER met2 ;
        RECT 172.590 0.000 172.870 4.000 ;
    END
  END X_real[36]
  PIN X_real[37]
    DIRECTION OUTPUT TRISTATE ;
    USE SIGNAL ;
    PORT
      LAYER met2 ;
        RECT 78.290 0.000 78.570 4.000 ;
    END
  END X_real[37]
  PIN X_real[38]
    DIRECTION OUTPUT TRISTATE ;
    USE SIGNAL ;
    PORT
      LAYER met3 ;
        RECT 667.705 673.240 671.705 673.840 ;
    END
  END X_real[38]
  PIN X_real[39]
    DIRECTION OUTPUT TRISTATE ;
    USE SIGNAL ;
    PORT
      LAYER met2 ;
        RECT 280.690 0.000 280.970 4.000 ;
    END
  END X_real[39]
  PIN X_real[3]
    DIRECTION OUTPUT TRISTATE ;
    USE SIGNAL ;
    PORT
      LAYER met3 ;
        RECT 0.000 353.640 4.000 354.240 ;
    END
  END X_real[3]
  PIN X_real[40]
    DIRECTION OUTPUT TRISTATE ;
    USE SIGNAL ;
    PORT
      LAYER met2 ;
        RECT 315.190 678.425 315.470 682.425 ;
    END
  END X_real[40]
  PIN X_real[41]
    DIRECTION OUTPUT TRISTATE ;
    USE SIGNAL ;
    PORT
      LAYER met3 ;
        RECT 667.705 57.840 671.705 58.440 ;
    END
  END X_real[41]
  PIN X_real[42]
    DIRECTION OUTPUT TRISTATE ;
    USE SIGNAL ;
    PORT
      LAYER met2 ;
        RECT 434.790 678.425 435.070 682.425 ;
    END
  END X_real[42]
  PIN X_real[43]
    DIRECTION OUTPUT TRISTATE ;
    USE SIGNAL ;
    PORT
      LAYER met3 ;
        RECT 667.705 350.240 671.705 350.840 ;
    END
  END X_real[43]
  PIN X_real[44]
    DIRECTION OUTPUT TRISTATE ;
    USE SIGNAL ;
    PORT
      LAYER met2 ;
        RECT 365.790 0.000 366.070 4.000 ;
    END
  END X_real[44]
  PIN X_real[45]
    DIRECTION OUTPUT TRISTATE ;
    USE SIGNAL ;
    PORT
      LAYER met2 ;
        RECT 632.590 0.000 632.870 4.000 ;
    END
  END X_real[45]
  PIN X_real[46]
    DIRECTION OUTPUT TRISTATE ;
    USE SIGNAL ;
    PORT
      LAYER met2 ;
        RECT 156.490 0.000 156.770 4.000 ;
    END
  END X_real[46]
  PIN X_real[47]
    DIRECTION OUTPUT TRISTATE ;
    USE SIGNAL ;
    PORT
      LAYER met2 ;
        RECT 563.590 0.000 563.870 4.000 ;
    END
  END X_real[47]
  PIN X_real[48]
    DIRECTION OUTPUT TRISTATE ;
    USE SIGNAL ;
    PORT
      LAYER met2 ;
        RECT 103.590 0.000 103.870 4.000 ;
    END
  END X_real[48]
  PIN X_real[49]
    DIRECTION OUTPUT TRISTATE ;
    USE SIGNAL ;
    PORT
      LAYER met2 ;
        RECT 115.090 678.425 115.370 682.425 ;
    END
  END X_real[49]
  PIN X_real[4]
    DIRECTION OUTPUT TRISTATE ;
    USE SIGNAL ;
    PORT
      LAYER met2 ;
        RECT 588.890 0.000 589.170 4.000 ;
    END
  END X_real[4]
  PIN X_real[50]
    DIRECTION OUTPUT TRISTATE ;
    USE SIGNAL ;
    PORT
      LAYER met2 ;
        RECT 630.290 678.425 630.570 682.425 ;
    END
  END X_real[50]
  PIN X_real[51]
    DIRECTION OUTPUT TRISTATE ;
    USE SIGNAL ;
    PORT
      LAYER met2 ;
        RECT 144.990 0.000 145.270 4.000 ;
    END
  END X_real[51]
  PIN X_real[52]
    DIRECTION OUTPUT TRISTATE ;
    USE SIGNAL ;
    PORT
      LAYER met3 ;
        RECT 667.705 227.840 671.705 228.440 ;
    END
  END X_real[52]
  PIN X_real[53]
    DIRECTION OUTPUT TRISTATE ;
    USE SIGNAL ;
    PORT
      LAYER met2 ;
        RECT 579.690 0.000 579.970 4.000 ;
    END
  END X_real[53]
  PIN X_real[54]
    DIRECTION OUTPUT TRISTATE ;
    USE SIGNAL ;
    PORT
      LAYER met2 ;
        RECT 379.590 0.000 379.870 4.000 ;
    END
  END X_real[54]
  PIN X_real[55]
    DIRECTION OUTPUT TRISTATE ;
    USE SIGNAL ;
    PORT
      LAYER met3 ;
        RECT 667.705 142.840 671.705 143.440 ;
    END
  END X_real[55]
  PIN X_real[56]
    DIRECTION OUTPUT TRISTATE ;
    USE SIGNAL ;
    PORT
      LAYER met2 ;
        RECT 66.790 0.000 67.070 4.000 ;
    END
  END X_real[56]
  PIN X_real[57]
    DIRECTION OUTPUT TRISTATE ;
    USE SIGNAL ;
    PORT
      LAYER met2 ;
        RECT 363.490 0.000 363.770 4.000 ;
    END
  END X_real[57]
  PIN X_real[58]
    DIRECTION OUTPUT TRISTATE ;
    USE SIGNAL ;
    PORT
      LAYER met3 ;
        RECT 0.000 44.240 4.000 44.840 ;
    END
  END X_real[58]
  PIN X_real[59]
    DIRECTION OUTPUT TRISTATE ;
    USE SIGNAL ;
    PORT
      LAYER met2 ;
        RECT 655.590 678.425 655.870 682.425 ;
    END
  END X_real[59]
  PIN X_real[5]
    DIRECTION OUTPUT TRISTATE ;
    USE SIGNAL ;
    PORT
      LAYER met3 ;
        RECT 667.705 217.640 671.705 218.240 ;
    END
  END X_real[5]
  PIN X_real[60]
    DIRECTION OUTPUT TRISTATE ;
    USE SIGNAL ;
    PORT
      LAYER met2 ;
        RECT 27.690 678.425 27.970 682.425 ;
    END
  END X_real[60]
  PIN X_real[61]
    DIRECTION OUTPUT TRISTATE ;
    USE SIGNAL ;
    PORT
      LAYER met3 ;
        RECT 0.000 397.840 4.000 398.440 ;
    END
  END X_real[61]
  PIN X_real[62]
    DIRECTION OUTPUT TRISTATE ;
    USE SIGNAL ;
    PORT
      LAYER met3 ;
        RECT 667.705 278.840 671.705 279.440 ;
    END
  END X_real[62]
  PIN X_real[63]
    DIRECTION OUTPUT TRISTATE ;
    USE SIGNAL ;
    PORT
      LAYER met2 ;
        RECT 202.490 0.000 202.770 4.000 ;
    END
  END X_real[63]
  PIN X_real[64]
    DIRECTION OUTPUT TRISTATE ;
    USE SIGNAL ;
    PORT
      LAYER met2 ;
        RECT 170.290 0.000 170.570 4.000 ;
    END
  END X_real[64]
  PIN X_real[65]
    DIRECTION OUTPUT TRISTATE ;
    USE SIGNAL ;
    PORT
      LAYER met2 ;
        RECT 39.190 0.000 39.470 4.000 ;
    END
  END X_real[65]
  PIN X_real[66]
    DIRECTION OUTPUT TRISTATE ;
    USE SIGNAL ;
    PORT
      LAYER met2 ;
        RECT 264.590 0.000 264.870 4.000 ;
    END
  END X_real[66]
  PIN X_real[67]
    DIRECTION OUTPUT TRISTATE ;
    USE SIGNAL ;
    PORT
      LAYER met2 ;
        RECT 471.590 678.425 471.870 682.425 ;
    END
  END X_real[67]
  PIN X_real[68]
    DIRECTION OUTPUT TRISTATE ;
    USE SIGNAL ;
    PORT
      LAYER met2 ;
        RECT 133.490 678.425 133.770 682.425 ;
    END
  END X_real[68]
  PIN X_real[69]
    DIRECTION OUTPUT TRISTATE ;
    USE SIGNAL ;
    PORT
      LAYER met3 ;
        RECT 0.000 656.240 4.000 656.840 ;
    END
  END X_real[69]
  PIN X_real[6]
    DIRECTION OUTPUT TRISTATE ;
    USE SIGNAL ;
    PORT
      LAYER met3 ;
        RECT 667.705 612.040 671.705 612.640 ;
    END
  END X_real[6]
  PIN X_real[70]
    DIRECTION OUTPUT TRISTATE ;
    USE SIGNAL ;
    PORT
      LAYER met2 ;
        RECT 52.990 678.425 53.270 682.425 ;
    END
  END X_real[70]
  PIN X_real[71]
    DIRECTION OUTPUT TRISTATE ;
    USE SIGNAL ;
    PORT
      LAYER met3 ;
        RECT 667.705 115.640 671.705 116.240 ;
    END
  END X_real[71]
  PIN X_real[72]
    DIRECTION OUTPUT TRISTATE ;
    USE SIGNAL ;
    PORT
      LAYER met2 ;
        RECT 220.890 678.425 221.170 682.425 ;
    END
  END X_real[72]
  PIN X_real[73]
    DIRECTION OUTPUT TRISTATE ;
    USE SIGNAL ;
    PORT
      LAYER met2 ;
        RECT 78.290 678.425 78.570 682.425 ;
    END
  END X_real[73]
  PIN X_real[74]
    DIRECTION OUTPUT TRISTATE ;
    USE SIGNAL ;
    PORT
      LAYER met2 ;
        RECT 190.990 0.000 191.270 4.000 ;
    END
  END X_real[74]
  PIN X_real[75]
    DIRECTION OUTPUT TRISTATE ;
    USE SIGNAL ;
    PORT
      LAYER met3 ;
        RECT 667.705 363.840 671.705 364.440 ;
    END
  END X_real[75]
  PIN X_real[76]
    DIRECTION OUTPUT TRISTATE ;
    USE SIGNAL ;
    PORT
      LAYER met2 ;
        RECT 515.290 0.000 515.570 4.000 ;
    END
  END X_real[76]
  PIN X_real[77]
    DIRECTION OUTPUT TRISTATE ;
    USE SIGNAL ;
    PORT
      LAYER met3 ;
        RECT 0.000 129.240 4.000 129.840 ;
    END
  END X_real[77]
  PIN X_real[78]
    DIRECTION OUTPUT TRISTATE ;
    USE SIGNAL ;
    PORT
      LAYER met2 ;
        RECT 82.890 0.000 83.170 4.000 ;
    END
  END X_real[78]
  PIN X_real[79]
    DIRECTION OUTPUT TRISTATE ;
    USE SIGNAL ;
    PORT
      LAYER met3 ;
        RECT 0.000 425.040 4.000 425.640 ;
    END
  END X_real[79]
  PIN X_real[7]
    DIRECTION OUTPUT TRISTATE ;
    USE SIGNAL ;
    PORT
      LAYER met2 ;
        RECT 246.190 678.425 246.470 682.425 ;
    END
  END X_real[7]
  PIN X_real[80]
    DIRECTION OUTPUT TRISTATE ;
    USE SIGNAL ;
    PORT
      LAYER met2 ;
        RECT 510.690 0.000 510.970 4.000 ;
    END
  END X_real[80]
  PIN X_real[81]
    DIRECTION OUTPUT TRISTATE ;
    USE SIGNAL ;
    PORT
      LAYER met3 ;
        RECT 0.000 431.840 4.000 432.440 ;
    END
  END X_real[81]
  PIN X_real[82]
    DIRECTION OUTPUT TRISTATE ;
    USE SIGNAL ;
    PORT
      LAYER met3 ;
        RECT 667.705 64.640 671.705 65.240 ;
    END
  END X_real[82]
  PIN X_real[83]
    DIRECTION OUTPUT TRISTATE ;
    USE SIGNAL ;
    PORT
      LAYER met2 ;
        RECT 542.890 0.000 543.170 4.000 ;
    END
  END X_real[83]
  PIN X_real[84]
    DIRECTION OUTPUT TRISTATE ;
    USE SIGNAL ;
    PORT
      LAYER met3 ;
        RECT 0.000 285.640 4.000 286.240 ;
    END
  END X_real[84]
  PIN X_real[85]
    DIRECTION OUTPUT TRISTATE ;
    USE SIGNAL ;
    PORT
      LAYER met3 ;
        RECT 0.000 530.440 4.000 531.040 ;
    END
  END X_real[85]
  PIN X_real[86]
    DIRECTION OUTPUT TRISTATE ;
    USE SIGNAL ;
    PORT
      LAYER met2 ;
        RECT 575.090 0.000 575.370 4.000 ;
    END
  END X_real[86]
  PIN X_real[87]
    DIRECTION OUTPUT TRISTATE ;
    USE SIGNAL ;
    PORT
      LAYER met2 ;
        RECT 395.690 0.000 395.970 4.000 ;
    END
  END X_real[87]
  PIN X_real[88]
    DIRECTION OUTPUT TRISTATE ;
    USE SIGNAL ;
    PORT
      LAYER met3 ;
        RECT 667.705 367.240 671.705 367.840 ;
    END
  END X_real[88]
  PIN X_real[89]
    DIRECTION OUTPUT TRISTATE ;
    USE SIGNAL ;
    PORT
      LAYER met2 ;
        RECT 55.290 0.000 55.570 4.000 ;
    END
  END X_real[89]
  PIN X_real[8]
    DIRECTION OUTPUT TRISTATE ;
    USE SIGNAL ;
    PORT
      LAYER met3 ;
        RECT 0.000 554.240 4.000 554.840 ;
    END
  END X_real[8]
  PIN X_real[90]
    DIRECTION OUTPUT TRISTATE ;
    USE SIGNAL ;
    PORT
      LAYER met3 ;
        RECT 0.000 571.240 4.000 571.840 ;
    END
  END X_real[90]
  PIN X_real[91]
    DIRECTION OUTPUT TRISTATE ;
    USE SIGNAL ;
    PORT
      LAYER met2 ;
        RECT 639.490 678.425 639.770 682.425 ;
    END
  END X_real[91]
  PIN X_real[92]
    DIRECTION OUTPUT TRISTATE ;
    USE SIGNAL ;
    PORT
      LAYER met2 ;
        RECT 621.090 0.000 621.370 4.000 ;
    END
  END X_real[92]
  PIN X_real[93]
    DIRECTION OUTPUT TRISTATE ;
    USE SIGNAL ;
    PORT
      LAYER met2 ;
        RECT 34.590 0.000 34.870 4.000 ;
    END
  END X_real[93]
  PIN X_real[94]
    DIRECTION OUTPUT TRISTATE ;
    USE SIGNAL ;
    PORT
      LAYER met3 ;
        RECT 667.705 319.640 671.705 320.240 ;
    END
  END X_real[94]
  PIN X_real[95]
    DIRECTION OUTPUT TRISTATE ;
    USE SIGNAL ;
    PORT
      LAYER met3 ;
        RECT 0.000 74.840 4.000 75.440 ;
    END
  END X_real[95]
  PIN X_real[96]
    DIRECTION OUTPUT TRISTATE ;
    USE SIGNAL ;
    PORT
      LAYER met3 ;
        RECT 0.000 91.840 4.000 92.440 ;
    END
  END X_real[96]
  PIN X_real[97]
    DIRECTION OUTPUT TRISTATE ;
    USE SIGNAL ;
    PORT
      LAYER met3 ;
        RECT 667.705 567.840 671.705 568.440 ;
    END
  END X_real[97]
  PIN X_real[98]
    DIRECTION OUTPUT TRISTATE ;
    USE SIGNAL ;
    PORT
      LAYER met2 ;
        RECT 18.490 0.000 18.770 4.000 ;
    END
  END X_real[98]
  PIN X_real[99]
    DIRECTION OUTPUT TRISTATE ;
    USE SIGNAL ;
    PORT
      LAYER met3 ;
        RECT 0.000 367.240 4.000 367.840 ;
    END
  END X_real[99]
  PIN X_real[9]
    DIRECTION OUTPUT TRISTATE ;
    USE SIGNAL ;
    PORT
      LAYER met2 ;
        RECT 75.990 0.000 76.270 4.000 ;
    END
  END X_real[9]
  PIN clk
    DIRECTION INPUT ;
    USE SIGNAL ;
    PORT
      LAYER met2 ;
        RECT 119.690 0.000 119.970 4.000 ;
    END
  END clk
  PIN rst_n
    DIRECTION INPUT ;
    USE SIGNAL ;
    PORT
      LAYER met2 ;
        RECT 487.690 678.425 487.970 682.425 ;
    END
  END rst_n
  PIN valid_in
    DIRECTION INPUT ;
    USE SIGNAL ;
    PORT
      LAYER met2 ;
        RECT 618.790 678.425 619.070 682.425 ;
    END
  END valid_in
  PIN valid_out
    DIRECTION OUTPUT TRISTATE ;
    USE SIGNAL ;
    PORT
      LAYER met2 ;
        RECT 501.490 0.000 501.770 4.000 ;
    END
  END valid_out
  PIN x_imag[0]
    DIRECTION INPUT ;
    USE SIGNAL ;
    PORT
      LAYER met3 ;
        RECT 0.000 591.640 4.000 592.240 ;
    END
  END x_imag[0]
  PIN x_imag[10]
    DIRECTION INPUT ;
    USE SIGNAL ;
    PORT
      LAYER met2 ;
        RECT 616.490 0.000 616.770 4.000 ;
    END
  END x_imag[10]
  PIN x_imag[11]
    DIRECTION INPUT ;
    USE SIGNAL ;
    PORT
      LAYER met2 ;
        RECT 478.490 678.425 478.770 682.425 ;
    END
  END x_imag[11]
  PIN x_imag[12]
    DIRECTION INPUT ;
    USE SIGNAL ;
    PORT
      LAYER met2 ;
        RECT 112.790 0.000 113.070 4.000 ;
    END
  END x_imag[12]
  PIN x_imag[13]
    DIRECTION INPUT ;
    USE SIGNAL ;
    PORT
      LAYER met2 ;
        RECT 644.090 678.425 644.370 682.425 ;
    END
  END x_imag[13]
  PIN x_imag[14]
    DIRECTION INPUT ;
    USE SIGNAL ;
    PORT
      LAYER met2 ;
        RECT 287.590 0.000 287.870 4.000 ;
    END
  END x_imag[14]
  PIN x_imag[15]
    DIRECTION INPUT ;
    USE SIGNAL ;
    PORT
      LAYER met3 ;
        RECT 0.000 370.640 4.000 371.240 ;
    END
  END x_imag[15]
  PIN x_imag[1]
    DIRECTION INPUT ;
    USE SIGNAL ;
    PORT
      LAYER met3 ;
        RECT 667.705 204.040 671.705 204.640 ;
    END
  END x_imag[1]
  PIN x_imag[2]
    DIRECTION INPUT ;
    USE SIGNAL ;
    PORT
      LAYER met3 ;
        RECT 667.705 17.040 671.705 17.640 ;
    END
  END x_imag[2]
  PIN x_imag[3]
    DIRECTION INPUT ;
    USE SIGNAL ;
    PORT
      LAYER met2 ;
        RECT 439.390 0.000 439.670 4.000 ;
    END
  END x_imag[3]
  PIN x_imag[4]
    DIRECTION INPUT ;
    USE SIGNAL ;
    PORT
      LAYER met2 ;
        RECT 322.090 0.000 322.370 4.000 ;
    END
  END x_imag[4]
  PIN x_imag[5]
    DIRECTION INPUT ;
    USE SIGNAL ;
    PORT
      LAYER met2 ;
        RECT 174.890 678.425 175.170 682.425 ;
    END
  END x_imag[5]
  PIN x_imag[6]
    DIRECTION INPUT ;
    USE SIGNAL ;
    PORT
      LAYER met2 ;
        RECT 310.590 678.425 310.870 682.425 ;
    END
  END x_imag[6]
  PIN x_imag[7]
    DIRECTION INPUT ;
    USE SIGNAL ;
    PORT
      LAYER met2 ;
        RECT 485.390 0.000 485.670 4.000 ;
    END
  END x_imag[7]
  PIN x_imag[8]
    DIRECTION INPUT ;
    USE SIGNAL ;
    PORT
      LAYER met3 ;
        RECT 667.705 88.440 671.705 89.040 ;
    END
  END x_imag[8]
  PIN x_imag[9]
    DIRECTION INPUT ;
    USE SIGNAL ;
    PORT
      LAYER met3 ;
        RECT 667.705 564.440 671.705 565.040 ;
    END
  END x_imag[9]
  PIN x_real[0]
    DIRECTION INPUT ;
    USE SIGNAL ;
    PORT
      LAYER met3 ;
        RECT 667.705 234.640 671.705 235.240 ;
    END
  END x_real[0]
  PIN x_real[10]
    DIRECTION INPUT ;
    USE SIGNAL ;
    PORT
      LAYER met3 ;
        RECT 667.705 210.840 671.705 211.440 ;
    END
  END x_real[10]
  PIN x_real[11]
    DIRECTION INPUT ;
    USE SIGNAL ;
    PORT
      LAYER met2 ;
        RECT 556.690 678.425 556.970 682.425 ;
    END
  END x_real[11]
  PIN x_real[12]
    DIRECTION INPUT ;
    USE SIGNAL ;
    PORT
      LAYER met2 ;
        RECT 648.690 0.000 648.970 4.000 ;
    END
  END x_real[12]
  PIN x_real[13]
    DIRECTION INPUT ;
    USE SIGNAL ;
    PORT
      LAYER met2 ;
        RECT 361.190 678.425 361.470 682.425 ;
    END
  END x_real[13]
  PIN x_real[14]
    DIRECTION INPUT ;
    USE SIGNAL ;
    PORT
      LAYER met3 ;
        RECT 667.705 302.640 671.705 303.240 ;
    END
  END x_real[14]
  PIN x_real[15]
    DIRECTION INPUT ;
    USE SIGNAL ;
    PORT
      LAYER met3 ;
        RECT 667.705 544.040 671.705 544.640 ;
    END
  END x_real[15]
  PIN x_real[1]
    DIRECTION INPUT ;
    USE SIGNAL ;
    PORT
      LAYER met2 ;
        RECT 253.090 678.425 253.370 682.425 ;
    END
  END x_real[1]
  PIN x_real[2]
    DIRECTION INPUT ;
    USE SIGNAL ;
    PORT
      LAYER met3 ;
        RECT 0.000 421.640 4.000 422.240 ;
    END
  END x_real[2]
  PIN x_real[3]
    DIRECTION INPUT ;
    USE SIGNAL ;
    PORT
      LAYER met2 ;
        RECT 625.690 0.000 625.970 4.000 ;
    END
  END x_real[3]
  PIN x_real[4]
    DIRECTION INPUT ;
    USE SIGNAL ;
    PORT
      LAYER met2 ;
        RECT 650.990 678.425 651.270 682.425 ;
    END
  END x_real[4]
  PIN x_real[5]
    DIRECTION INPUT ;
    USE SIGNAL ;
    PORT
      LAYER met2 ;
        RECT 416.390 0.000 416.670 4.000 ;
    END
  END x_real[5]
  PIN x_real[6]
    DIRECTION INPUT ;
    USE SIGNAL ;
    PORT
      LAYER met3 ;
        RECT 667.705 102.040 671.705 102.640 ;
    END
  END x_real[6]
  PIN x_real[7]
    DIRECTION INPUT ;
    USE SIGNAL ;
    PORT
      LAYER met2 ;
        RECT 545.190 678.425 545.470 682.425 ;
    END
  END x_real[7]
  PIN x_real[8]
    DIRECTION INPUT ;
    USE SIGNAL ;
    PORT
      LAYER met3 ;
        RECT 667.705 605.240 671.705 605.840 ;
    END
  END x_real[8]
  PIN x_real[9]
    DIRECTION INPUT ;
    USE SIGNAL ;
    PORT
      LAYER met2 ;
        RECT 41.490 0.000 41.770 4.000 ;
    END
  END x_real[9]
  PIN VPWR
    DIRECTION INOUT ;
    USE POWER ;
    PORT
      LAYER met4 ;
        RECT 635.440 10.640 637.040 669.360 ;
    END
  END VPWR
  PIN VPWR
    DIRECTION INOUT ;
    USE POWER ;
    PORT
      LAYER met4 ;
        RECT 481.840 10.640 483.440 669.360 ;
    END
  END VPWR
  PIN VPWR
    DIRECTION INOUT ;
    USE POWER ;
    PORT
      LAYER met4 ;
        RECT 328.240 10.640 329.840 669.360 ;
    END
  END VPWR
  PIN VPWR
    DIRECTION INOUT ;
    USE POWER ;
    PORT
      LAYER met4 ;
        RECT 174.640 10.640 176.240 669.360 ;
    END
  END VPWR
  PIN VPWR
    DIRECTION INOUT ;
    USE POWER ;
    PORT
      LAYER met4 ;
        RECT 21.040 10.640 22.640 669.360 ;
    END
  END VPWR
  PIN VPWR
    DIRECTION INOUT ;
    USE POWER ;
    PORT
      LAYER met5 ;
        RECT 5.520 639.210 666.080 640.810 ;
    END
  END VPWR
  PIN VPWR
    DIRECTION INOUT ;
    USE POWER ;
    PORT
      LAYER met5 ;
        RECT 5.520 486.030 666.080 487.630 ;
    END
  END VPWR
  PIN VPWR
    DIRECTION INOUT ;
    USE POWER ;
    PORT
      LAYER met5 ;
        RECT 5.520 332.850 666.080 334.450 ;
    END
  END VPWR
  PIN VPWR
    DIRECTION INOUT ;
    USE POWER ;
    PORT
      LAYER met5 ;
        RECT 5.520 179.670 666.080 181.270 ;
    END
  END VPWR
  PIN VPWR
    DIRECTION INOUT ;
    USE POWER ;
    PORT
      LAYER met5 ;
        RECT 5.520 26.490 666.080 28.090 ;
    END
  END VPWR
  PIN VGND
    DIRECTION INOUT ;
    USE GROUND ;
    PORT
      LAYER met4 ;
        RECT 558.640 10.640 560.240 669.360 ;
    END
  END VGND
  PIN VGND
    DIRECTION INOUT ;
    USE GROUND ;
    PORT
      LAYER met4 ;
        RECT 405.040 10.640 406.640 669.360 ;
    END
  END VGND
  PIN VGND
    DIRECTION INOUT ;
    USE GROUND ;
    PORT
      LAYER met4 ;
        RECT 251.440 10.640 253.040 669.360 ;
    END
  END VGND
  PIN VGND
    DIRECTION INOUT ;
    USE GROUND ;
    PORT
      LAYER met4 ;
        RECT 97.840 10.640 99.440 669.360 ;
    END
  END VGND
  PIN VGND
    DIRECTION INOUT ;
    USE GROUND ;
    PORT
      LAYER met5 ;
        RECT 5.520 562.620 666.080 564.220 ;
    END
  END VGND
  PIN VGND
    DIRECTION INOUT ;
    USE GROUND ;
    PORT
      LAYER met5 ;
        RECT 5.520 409.440 666.080 411.040 ;
    END
  END VGND
  PIN VGND
    DIRECTION INOUT ;
    USE GROUND ;
    PORT
      LAYER met5 ;
        RECT 5.520 256.260 666.080 257.860 ;
    END
  END VGND
  PIN VGND
    DIRECTION INOUT ;
    USE GROUND ;
    PORT
      LAYER met5 ;
        RECT 5.520 103.080 666.080 104.680 ;
    END
  END VGND
  OBS
      LAYER li1 ;
        RECT 3.365 8.925 669.155 669.205 ;
      LAYER met1 ;
        RECT 0.070 6.840 671.530 669.360 ;
      LAYER met2 ;
        RECT 0.100 678.145 2.110 678.425 ;
        RECT 2.950 678.145 6.710 678.425 ;
        RECT 7.550 678.145 11.310 678.425 ;
        RECT 12.150 678.145 15.910 678.425 ;
        RECT 16.750 678.145 20.510 678.425 ;
        RECT 21.350 678.145 22.810 678.425 ;
        RECT 23.650 678.145 27.410 678.425 ;
        RECT 28.250 678.145 32.010 678.425 ;
        RECT 32.850 678.145 36.610 678.425 ;
        RECT 37.450 678.145 38.910 678.425 ;
        RECT 39.750 678.145 43.510 678.425 ;
        RECT 44.350 678.145 48.110 678.425 ;
        RECT 48.950 678.145 52.710 678.425 ;
        RECT 53.550 678.145 57.310 678.425 ;
        RECT 58.150 678.145 59.610 678.425 ;
        RECT 60.450 678.145 64.210 678.425 ;
        RECT 65.050 678.145 68.810 678.425 ;
        RECT 69.650 678.145 73.410 678.425 ;
        RECT 74.250 678.145 78.010 678.425 ;
        RECT 78.850 678.145 80.310 678.425 ;
        RECT 81.150 678.145 84.910 678.425 ;
        RECT 85.750 678.145 89.510 678.425 ;
        RECT 90.350 678.145 94.110 678.425 ;
        RECT 94.950 678.145 96.410 678.425 ;
        RECT 97.250 678.145 101.010 678.425 ;
        RECT 101.850 678.145 105.610 678.425 ;
        RECT 106.450 678.145 110.210 678.425 ;
        RECT 111.050 678.145 114.810 678.425 ;
        RECT 115.650 678.145 117.110 678.425 ;
        RECT 117.950 678.145 121.710 678.425 ;
        RECT 122.550 678.145 126.310 678.425 ;
        RECT 127.150 678.145 130.910 678.425 ;
        RECT 131.750 678.145 133.210 678.425 ;
        RECT 134.050 678.145 137.810 678.425 ;
        RECT 138.650 678.145 142.410 678.425 ;
        RECT 143.250 678.145 147.010 678.425 ;
        RECT 147.850 678.145 151.610 678.425 ;
        RECT 152.450 678.145 153.910 678.425 ;
        RECT 154.750 678.145 158.510 678.425 ;
        RECT 159.350 678.145 163.110 678.425 ;
        RECT 163.950 678.145 167.710 678.425 ;
        RECT 168.550 678.145 172.310 678.425 ;
        RECT 173.150 678.145 174.610 678.425 ;
        RECT 175.450 678.145 179.210 678.425 ;
        RECT 180.050 678.145 183.810 678.425 ;
        RECT 184.650 678.145 188.410 678.425 ;
        RECT 189.250 678.145 190.710 678.425 ;
        RECT 191.550 678.145 195.310 678.425 ;
        RECT 196.150 678.145 199.910 678.425 ;
        RECT 200.750 678.145 204.510 678.425 ;
        RECT 205.350 678.145 209.110 678.425 ;
        RECT 209.950 678.145 211.410 678.425 ;
        RECT 212.250 678.145 216.010 678.425 ;
        RECT 216.850 678.145 220.610 678.425 ;
        RECT 221.450 678.145 225.210 678.425 ;
        RECT 226.050 678.145 229.810 678.425 ;
        RECT 230.650 678.145 232.110 678.425 ;
        RECT 232.950 678.145 236.710 678.425 ;
        RECT 237.550 678.145 241.310 678.425 ;
        RECT 242.150 678.145 245.910 678.425 ;
        RECT 246.750 678.145 248.210 678.425 ;
        RECT 249.050 678.145 252.810 678.425 ;
        RECT 253.650 678.145 257.410 678.425 ;
        RECT 258.250 678.145 262.010 678.425 ;
        RECT 262.850 678.145 266.610 678.425 ;
        RECT 267.450 678.145 268.910 678.425 ;
        RECT 269.750 678.145 273.510 678.425 ;
        RECT 274.350 678.145 278.110 678.425 ;
        RECT 278.950 678.145 282.710 678.425 ;
        RECT 283.550 678.145 287.310 678.425 ;
        RECT 288.150 678.145 289.610 678.425 ;
        RECT 290.450 678.145 294.210 678.425 ;
        RECT 295.050 678.145 298.810 678.425 ;
        RECT 299.650 678.145 303.410 678.425 ;
        RECT 304.250 678.145 305.710 678.425 ;
        RECT 306.550 678.145 310.310 678.425 ;
        RECT 311.150 678.145 314.910 678.425 ;
        RECT 315.750 678.145 319.510 678.425 ;
        RECT 320.350 678.145 324.110 678.425 ;
        RECT 324.950 678.145 326.410 678.425 ;
        RECT 327.250 678.145 331.010 678.425 ;
        RECT 331.850 678.145 335.610 678.425 ;
        RECT 336.450 678.145 340.210 678.425 ;
        RECT 341.050 678.145 344.810 678.425 ;
        RECT 345.650 678.145 347.110 678.425 ;
        RECT 347.950 678.145 351.710 678.425 ;
        RECT 352.550 678.145 356.310 678.425 ;
        RECT 357.150 678.145 360.910 678.425 ;
        RECT 361.750 678.145 363.210 678.425 ;
        RECT 364.050 678.145 367.810 678.425 ;
        RECT 368.650 678.145 372.410 678.425 ;
        RECT 373.250 678.145 377.010 678.425 ;
        RECT 377.850 678.145 381.610 678.425 ;
        RECT 382.450 678.145 383.910 678.425 ;
        RECT 384.750 678.145 388.510 678.425 ;
        RECT 389.350 678.145 393.110 678.425 ;
        RECT 393.950 678.145 397.710 678.425 ;
        RECT 398.550 678.145 400.010 678.425 ;
        RECT 400.850 678.145 404.610 678.425 ;
        RECT 405.450 678.145 409.210 678.425 ;
        RECT 410.050 678.145 413.810 678.425 ;
        RECT 414.650 678.145 418.410 678.425 ;
        RECT 419.250 678.145 420.710 678.425 ;
        RECT 421.550 678.145 425.310 678.425 ;
        RECT 426.150 678.145 429.910 678.425 ;
        RECT 430.750 678.145 434.510 678.425 ;
        RECT 435.350 678.145 439.110 678.425 ;
        RECT 439.950 678.145 441.410 678.425 ;
        RECT 442.250 678.145 446.010 678.425 ;
        RECT 446.850 678.145 450.610 678.425 ;
        RECT 451.450 678.145 455.210 678.425 ;
        RECT 456.050 678.145 457.510 678.425 ;
        RECT 458.350 678.145 462.110 678.425 ;
        RECT 462.950 678.145 466.710 678.425 ;
        RECT 467.550 678.145 471.310 678.425 ;
        RECT 472.150 678.145 475.910 678.425 ;
        RECT 476.750 678.145 478.210 678.425 ;
        RECT 479.050 678.145 482.810 678.425 ;
        RECT 483.650 678.145 487.410 678.425 ;
        RECT 488.250 678.145 492.010 678.425 ;
        RECT 492.850 678.145 496.610 678.425 ;
        RECT 497.450 678.145 498.910 678.425 ;
        RECT 499.750 678.145 503.510 678.425 ;
        RECT 504.350 678.145 508.110 678.425 ;
        RECT 508.950 678.145 512.710 678.425 ;
        RECT 513.550 678.145 515.010 678.425 ;
        RECT 515.850 678.145 519.610 678.425 ;
        RECT 520.450 678.145 524.210 678.425 ;
        RECT 525.050 678.145 528.810 678.425 ;
        RECT 529.650 678.145 533.410 678.425 ;
        RECT 534.250 678.145 535.710 678.425 ;
        RECT 536.550 678.145 540.310 678.425 ;
        RECT 541.150 678.145 544.910 678.425 ;
        RECT 545.750 678.145 549.510 678.425 ;
        RECT 550.350 678.145 554.110 678.425 ;
        RECT 554.950 678.145 556.410 678.425 ;
        RECT 557.250 678.145 561.010 678.425 ;
        RECT 561.850 678.145 565.610 678.425 ;
        RECT 566.450 678.145 570.210 678.425 ;
        RECT 571.050 678.145 572.510 678.425 ;
        RECT 573.350 678.145 577.110 678.425 ;
        RECT 577.950 678.145 581.710 678.425 ;
        RECT 582.550 678.145 586.310 678.425 ;
        RECT 587.150 678.145 590.910 678.425 ;
        RECT 591.750 678.145 593.210 678.425 ;
        RECT 594.050 678.145 597.810 678.425 ;
        RECT 598.650 678.145 602.410 678.425 ;
        RECT 603.250 678.145 607.010 678.425 ;
        RECT 607.850 678.145 611.610 678.425 ;
        RECT 612.450 678.145 613.910 678.425 ;
        RECT 614.750 678.145 618.510 678.425 ;
        RECT 619.350 678.145 623.110 678.425 ;
        RECT 623.950 678.145 627.710 678.425 ;
        RECT 628.550 678.145 630.010 678.425 ;
        RECT 630.850 678.145 634.610 678.425 ;
        RECT 635.450 678.145 639.210 678.425 ;
        RECT 640.050 678.145 643.810 678.425 ;
        RECT 644.650 678.145 648.410 678.425 ;
        RECT 649.250 678.145 650.710 678.425 ;
        RECT 651.550 678.145 655.310 678.425 ;
        RECT 656.150 678.145 659.910 678.425 ;
        RECT 660.750 678.145 664.510 678.425 ;
        RECT 665.350 678.145 666.810 678.425 ;
        RECT 667.650 678.145 671.500 678.425 ;
        RECT 0.100 4.280 671.500 678.145 ;
        RECT 0.100 3.555 2.110 4.280 ;
        RECT 2.950 3.555 4.410 4.280 ;
        RECT 5.250 3.555 9.010 4.280 ;
        RECT 9.850 3.555 13.610 4.280 ;
        RECT 14.450 3.555 18.210 4.280 ;
        RECT 19.050 3.555 20.510 4.280 ;
        RECT 21.350 3.555 25.110 4.280 ;
        RECT 25.950 3.555 29.710 4.280 ;
        RECT 30.550 3.555 34.310 4.280 ;
        RECT 35.150 3.555 38.910 4.280 ;
        RECT 39.750 3.555 41.210 4.280 ;
        RECT 42.050 3.555 45.810 4.280 ;
        RECT 46.650 3.555 50.410 4.280 ;
        RECT 51.250 3.555 55.010 4.280 ;
        RECT 55.850 3.555 57.310 4.280 ;
        RECT 58.150 3.555 61.910 4.280 ;
        RECT 62.750 3.555 66.510 4.280 ;
        RECT 67.350 3.555 71.110 4.280 ;
        RECT 71.950 3.555 75.710 4.280 ;
        RECT 76.550 3.555 78.010 4.280 ;
        RECT 78.850 3.555 82.610 4.280 ;
        RECT 83.450 3.555 87.210 4.280 ;
        RECT 88.050 3.555 91.810 4.280 ;
        RECT 92.650 3.555 96.410 4.280 ;
        RECT 97.250 3.555 98.710 4.280 ;
        RECT 99.550 3.555 103.310 4.280 ;
        RECT 104.150 3.555 107.910 4.280 ;
        RECT 108.750 3.555 112.510 4.280 ;
        RECT 113.350 3.555 114.810 4.280 ;
        RECT 115.650 3.555 119.410 4.280 ;
        RECT 120.250 3.555 124.010 4.280 ;
        RECT 124.850 3.555 128.610 4.280 ;
        RECT 129.450 3.555 133.210 4.280 ;
        RECT 134.050 3.555 135.510 4.280 ;
        RECT 136.350 3.555 140.110 4.280 ;
        RECT 140.950 3.555 144.710 4.280 ;
        RECT 145.550 3.555 149.310 4.280 ;
        RECT 150.150 3.555 153.910 4.280 ;
        RECT 154.750 3.555 156.210 4.280 ;
        RECT 157.050 3.555 160.810 4.280 ;
        RECT 161.650 3.555 165.410 4.280 ;
        RECT 166.250 3.555 170.010 4.280 ;
        RECT 170.850 3.555 172.310 4.280 ;
        RECT 173.150 3.555 176.910 4.280 ;
        RECT 177.750 3.555 181.510 4.280 ;
        RECT 182.350 3.555 186.110 4.280 ;
        RECT 186.950 3.555 190.710 4.280 ;
        RECT 191.550 3.555 193.010 4.280 ;
        RECT 193.850 3.555 197.610 4.280 ;
        RECT 198.450 3.555 202.210 4.280 ;
        RECT 203.050 3.555 206.810 4.280 ;
        RECT 207.650 3.555 211.410 4.280 ;
        RECT 212.250 3.555 213.710 4.280 ;
        RECT 214.550 3.555 218.310 4.280 ;
        RECT 219.150 3.555 222.910 4.280 ;
        RECT 223.750 3.555 227.510 4.280 ;
        RECT 228.350 3.555 229.810 4.280 ;
        RECT 230.650 3.555 234.410 4.280 ;
        RECT 235.250 3.555 239.010 4.280 ;
        RECT 239.850 3.555 243.610 4.280 ;
        RECT 244.450 3.555 248.210 4.280 ;
        RECT 249.050 3.555 250.510 4.280 ;
        RECT 251.350 3.555 255.110 4.280 ;
        RECT 255.950 3.555 259.710 4.280 ;
        RECT 260.550 3.555 264.310 4.280 ;
        RECT 265.150 3.555 268.910 4.280 ;
        RECT 269.750 3.555 271.210 4.280 ;
        RECT 272.050 3.555 275.810 4.280 ;
        RECT 276.650 3.555 280.410 4.280 ;
        RECT 281.250 3.555 285.010 4.280 ;
        RECT 285.850 3.555 287.310 4.280 ;
        RECT 288.150 3.555 291.910 4.280 ;
        RECT 292.750 3.555 296.510 4.280 ;
        RECT 297.350 3.555 301.110 4.280 ;
        RECT 301.950 3.555 305.710 4.280 ;
        RECT 306.550 3.555 308.010 4.280 ;
        RECT 308.850 3.555 312.610 4.280 ;
        RECT 313.450 3.555 317.210 4.280 ;
        RECT 318.050 3.555 321.810 4.280 ;
        RECT 322.650 3.555 324.110 4.280 ;
        RECT 324.950 3.555 328.710 4.280 ;
        RECT 329.550 3.555 333.310 4.280 ;
        RECT 334.150 3.555 337.910 4.280 ;
        RECT 338.750 3.555 342.510 4.280 ;
        RECT 343.350 3.555 344.810 4.280 ;
        RECT 345.650 3.555 349.410 4.280 ;
        RECT 350.250 3.555 354.010 4.280 ;
        RECT 354.850 3.555 358.610 4.280 ;
        RECT 359.450 3.555 363.210 4.280 ;
        RECT 364.050 3.555 365.510 4.280 ;
        RECT 366.350 3.555 370.110 4.280 ;
        RECT 370.950 3.555 374.710 4.280 ;
        RECT 375.550 3.555 379.310 4.280 ;
        RECT 380.150 3.555 381.610 4.280 ;
        RECT 382.450 3.555 386.210 4.280 ;
        RECT 387.050 3.555 390.810 4.280 ;
        RECT 391.650 3.555 395.410 4.280 ;
        RECT 396.250 3.555 400.010 4.280 ;
        RECT 400.850 3.555 402.310 4.280 ;
        RECT 403.150 3.555 406.910 4.280 ;
        RECT 407.750 3.555 411.510 4.280 ;
        RECT 412.350 3.555 416.110 4.280 ;
        RECT 416.950 3.555 420.710 4.280 ;
        RECT 421.550 3.555 423.010 4.280 ;
        RECT 423.850 3.555 427.610 4.280 ;
        RECT 428.450 3.555 432.210 4.280 ;
        RECT 433.050 3.555 436.810 4.280 ;
        RECT 437.650 3.555 439.110 4.280 ;
        RECT 439.950 3.555 443.710 4.280 ;
        RECT 444.550 3.555 448.310 4.280 ;
        RECT 449.150 3.555 452.910 4.280 ;
        RECT 453.750 3.555 457.510 4.280 ;
        RECT 458.350 3.555 459.810 4.280 ;
        RECT 460.650 3.555 464.410 4.280 ;
        RECT 465.250 3.555 469.010 4.280 ;
        RECT 469.850 3.555 473.610 4.280 ;
        RECT 474.450 3.555 478.210 4.280 ;
        RECT 479.050 3.555 480.510 4.280 ;
        RECT 481.350 3.555 485.110 4.280 ;
        RECT 485.950 3.555 489.710 4.280 ;
        RECT 490.550 3.555 494.310 4.280 ;
        RECT 495.150 3.555 496.610 4.280 ;
        RECT 497.450 3.555 501.210 4.280 ;
        RECT 502.050 3.555 505.810 4.280 ;
        RECT 506.650 3.555 510.410 4.280 ;
        RECT 511.250 3.555 515.010 4.280 ;
        RECT 515.850 3.555 517.310 4.280 ;
        RECT 518.150 3.555 521.910 4.280 ;
        RECT 522.750 3.555 526.510 4.280 ;
        RECT 527.350 3.555 531.110 4.280 ;
        RECT 531.950 3.555 535.710 4.280 ;
        RECT 536.550 3.555 538.010 4.280 ;
        RECT 538.850 3.555 542.610 4.280 ;
        RECT 543.450 3.555 547.210 4.280 ;
        RECT 548.050 3.555 551.810 4.280 ;
        RECT 552.650 3.555 554.110 4.280 ;
        RECT 554.950 3.555 558.710 4.280 ;
        RECT 559.550 3.555 563.310 4.280 ;
        RECT 564.150 3.555 567.910 4.280 ;
        RECT 568.750 3.555 572.510 4.280 ;
        RECT 573.350 3.555 574.810 4.280 ;
        RECT 575.650 3.555 579.410 4.280 ;
        RECT 580.250 3.555 584.010 4.280 ;
        RECT 584.850 3.555 588.610 4.280 ;
        RECT 589.450 3.555 590.910 4.280 ;
        RECT 591.750 3.555 595.510 4.280 ;
        RECT 596.350 3.555 600.110 4.280 ;
        RECT 600.950 3.555 604.710 4.280 ;
        RECT 605.550 3.555 609.310 4.280 ;
        RECT 610.150 3.555 611.610 4.280 ;
        RECT 612.450 3.555 616.210 4.280 ;
        RECT 617.050 3.555 620.810 4.280 ;
        RECT 621.650 3.555 625.410 4.280 ;
        RECT 626.250 3.555 630.010 4.280 ;
        RECT 630.850 3.555 632.310 4.280 ;
        RECT 633.150 3.555 636.910 4.280 ;
        RECT 637.750 3.555 641.510 4.280 ;
        RECT 642.350 3.555 646.110 4.280 ;
        RECT 646.950 3.555 648.410 4.280 ;
        RECT 649.250 3.555 653.010 4.280 ;
        RECT 653.850 3.555 657.610 4.280 ;
        RECT 658.450 3.555 662.210 4.280 ;
        RECT 663.050 3.555 666.810 4.280 ;
        RECT 667.650 3.555 671.500 4.280 ;
      LAYER met3 ;
        RECT 4.400 676.240 670.615 677.105 ;
        RECT 0.270 674.240 670.615 676.240 ;
        RECT 0.270 672.840 667.305 674.240 ;
        RECT 0.270 670.840 670.615 672.840 ;
        RECT 4.400 669.440 670.615 670.840 ;
        RECT 0.270 667.440 670.615 669.440 ;
        RECT 0.270 666.040 667.305 667.440 ;
        RECT 0.270 664.040 670.615 666.040 ;
        RECT 4.400 662.640 670.615 664.040 ;
        RECT 0.270 660.640 670.615 662.640 ;
        RECT 0.270 659.240 667.305 660.640 ;
        RECT 0.270 657.240 670.615 659.240 ;
        RECT 4.400 655.840 670.615 657.240 ;
        RECT 0.270 653.840 670.615 655.840 ;
        RECT 0.270 652.440 667.305 653.840 ;
        RECT 0.270 650.440 670.615 652.440 ;
        RECT 4.400 649.040 667.305 650.440 ;
        RECT 0.270 647.040 670.615 649.040 ;
        RECT 4.400 645.640 670.615 647.040 ;
        RECT 0.270 643.640 670.615 645.640 ;
        RECT 0.270 642.240 667.305 643.640 ;
        RECT 0.270 640.240 670.615 642.240 ;
        RECT 4.400 638.840 670.615 640.240 ;
        RECT 0.270 636.840 670.615 638.840 ;
        RECT 0.270 635.440 667.305 636.840 ;
        RECT 0.270 633.440 670.615 635.440 ;
        RECT 4.400 632.040 670.615 633.440 ;
        RECT 0.270 630.040 670.615 632.040 ;
        RECT 0.270 628.640 667.305 630.040 ;
        RECT 0.270 626.640 670.615 628.640 ;
        RECT 4.400 625.240 670.615 626.640 ;
        RECT 0.270 623.240 670.615 625.240 ;
        RECT 4.400 621.840 667.305 623.240 ;
        RECT 0.270 619.840 670.615 621.840 ;
        RECT 0.270 618.440 667.305 619.840 ;
        RECT 0.270 616.440 670.615 618.440 ;
        RECT 4.400 615.040 670.615 616.440 ;
        RECT 0.270 613.040 670.615 615.040 ;
        RECT 0.270 611.640 667.305 613.040 ;
        RECT 0.270 609.640 670.615 611.640 ;
        RECT 4.400 608.240 670.615 609.640 ;
        RECT 0.270 606.240 670.615 608.240 ;
        RECT 0.270 604.840 667.305 606.240 ;
        RECT 0.270 602.840 670.615 604.840 ;
        RECT 4.400 601.440 670.615 602.840 ;
        RECT 0.270 599.440 670.615 601.440 ;
        RECT 0.270 598.040 667.305 599.440 ;
        RECT 0.270 596.040 670.615 598.040 ;
        RECT 4.400 594.640 667.305 596.040 ;
        RECT 0.270 592.640 670.615 594.640 ;
        RECT 4.400 591.240 670.615 592.640 ;
        RECT 0.270 589.240 670.615 591.240 ;
        RECT 0.270 587.840 667.305 589.240 ;
        RECT 0.270 585.840 670.615 587.840 ;
        RECT 4.400 584.440 670.615 585.840 ;
        RECT 0.270 582.440 670.615 584.440 ;
        RECT 0.270 581.040 667.305 582.440 ;
        RECT 0.270 579.040 670.615 581.040 ;
        RECT 4.400 577.640 670.615 579.040 ;
        RECT 0.270 575.640 670.615 577.640 ;
        RECT 0.270 574.240 667.305 575.640 ;
        RECT 0.270 572.240 670.615 574.240 ;
        RECT 4.400 570.840 670.615 572.240 ;
        RECT 0.270 568.840 670.615 570.840 ;
        RECT 0.270 567.440 667.305 568.840 ;
        RECT 0.270 565.440 670.615 567.440 ;
        RECT 4.400 564.040 667.305 565.440 ;
        RECT 0.270 562.040 670.615 564.040 ;
        RECT 4.400 560.640 670.615 562.040 ;
        RECT 0.270 558.640 670.615 560.640 ;
        RECT 0.270 557.240 667.305 558.640 ;
        RECT 0.270 555.240 670.615 557.240 ;
        RECT 4.400 553.840 670.615 555.240 ;
        RECT 0.270 551.840 670.615 553.840 ;
        RECT 0.270 550.440 667.305 551.840 ;
        RECT 0.270 548.440 670.615 550.440 ;
        RECT 4.400 547.040 670.615 548.440 ;
        RECT 0.270 545.040 670.615 547.040 ;
        RECT 0.270 543.640 667.305 545.040 ;
        RECT 0.270 541.640 670.615 543.640 ;
        RECT 4.400 540.240 670.615 541.640 ;
        RECT 0.270 538.240 670.615 540.240 ;
        RECT 4.400 536.840 667.305 538.240 ;
        RECT 0.270 534.840 670.615 536.840 ;
        RECT 0.270 533.440 667.305 534.840 ;
        RECT 0.270 531.440 670.615 533.440 ;
        RECT 4.400 530.040 670.615 531.440 ;
        RECT 0.270 528.040 670.615 530.040 ;
        RECT 0.270 526.640 667.305 528.040 ;
        RECT 0.270 524.640 670.615 526.640 ;
        RECT 4.400 523.240 670.615 524.640 ;
        RECT 0.270 521.240 670.615 523.240 ;
        RECT 0.270 519.840 667.305 521.240 ;
        RECT 0.270 517.840 670.615 519.840 ;
        RECT 4.400 516.440 670.615 517.840 ;
        RECT 0.270 514.440 670.615 516.440 ;
        RECT 0.270 513.040 667.305 514.440 ;
        RECT 0.270 511.040 670.615 513.040 ;
        RECT 4.400 509.640 667.305 511.040 ;
        RECT 0.270 507.640 670.615 509.640 ;
        RECT 4.400 506.240 670.615 507.640 ;
        RECT 0.270 504.240 670.615 506.240 ;
        RECT 0.270 502.840 667.305 504.240 ;
        RECT 0.270 500.840 670.615 502.840 ;
        RECT 4.400 499.440 670.615 500.840 ;
        RECT 0.270 497.440 670.615 499.440 ;
        RECT 0.270 496.040 667.305 497.440 ;
        RECT 0.270 494.040 670.615 496.040 ;
        RECT 4.400 492.640 670.615 494.040 ;
        RECT 0.270 490.640 670.615 492.640 ;
        RECT 0.270 489.240 667.305 490.640 ;
        RECT 0.270 487.240 670.615 489.240 ;
        RECT 4.400 485.840 670.615 487.240 ;
        RECT 0.270 483.840 670.615 485.840 ;
        RECT 0.270 482.440 667.305 483.840 ;
        RECT 0.270 480.440 670.615 482.440 ;
        RECT 4.400 479.040 667.305 480.440 ;
        RECT 0.270 477.040 670.615 479.040 ;
        RECT 4.400 475.640 670.615 477.040 ;
        RECT 0.270 473.640 670.615 475.640 ;
        RECT 0.270 472.240 667.305 473.640 ;
        RECT 0.270 470.240 670.615 472.240 ;
        RECT 4.400 468.840 670.615 470.240 ;
        RECT 0.270 466.840 670.615 468.840 ;
        RECT 0.270 465.440 667.305 466.840 ;
        RECT 0.270 463.440 670.615 465.440 ;
        RECT 4.400 462.040 670.615 463.440 ;
        RECT 0.270 460.040 670.615 462.040 ;
        RECT 0.270 458.640 667.305 460.040 ;
        RECT 0.270 456.640 670.615 458.640 ;
        RECT 4.400 455.240 670.615 456.640 ;
        RECT 0.270 453.240 670.615 455.240 ;
        RECT 4.400 451.840 667.305 453.240 ;
        RECT 0.270 449.840 670.615 451.840 ;
        RECT 0.270 448.440 667.305 449.840 ;
        RECT 0.270 446.440 670.615 448.440 ;
        RECT 4.400 445.040 670.615 446.440 ;
        RECT 0.270 443.040 670.615 445.040 ;
        RECT 0.270 441.640 667.305 443.040 ;
        RECT 0.270 439.640 670.615 441.640 ;
        RECT 4.400 438.240 670.615 439.640 ;
        RECT 0.270 436.240 670.615 438.240 ;
        RECT 0.270 434.840 667.305 436.240 ;
        RECT 0.270 432.840 670.615 434.840 ;
        RECT 4.400 431.440 670.615 432.840 ;
        RECT 0.270 429.440 670.615 431.440 ;
        RECT 0.270 428.040 667.305 429.440 ;
        RECT 0.270 426.040 670.615 428.040 ;
        RECT 4.400 424.640 667.305 426.040 ;
        RECT 0.270 422.640 670.615 424.640 ;
        RECT 4.400 421.240 670.615 422.640 ;
        RECT 0.270 419.240 670.615 421.240 ;
        RECT 0.270 417.840 667.305 419.240 ;
        RECT 0.270 415.840 670.615 417.840 ;
        RECT 4.400 414.440 670.615 415.840 ;
        RECT 0.270 412.440 670.615 414.440 ;
        RECT 0.270 411.040 667.305 412.440 ;
        RECT 0.270 409.040 670.615 411.040 ;
        RECT 4.400 407.640 670.615 409.040 ;
        RECT 0.270 405.640 670.615 407.640 ;
        RECT 0.270 404.240 667.305 405.640 ;
        RECT 0.270 402.240 670.615 404.240 ;
        RECT 4.400 400.840 670.615 402.240 ;
        RECT 0.270 398.840 670.615 400.840 ;
        RECT 4.400 397.440 667.305 398.840 ;
        RECT 0.270 395.440 670.615 397.440 ;
        RECT 0.270 394.040 667.305 395.440 ;
        RECT 0.270 392.040 670.615 394.040 ;
        RECT 4.400 390.640 670.615 392.040 ;
        RECT 0.270 388.640 670.615 390.640 ;
        RECT 0.270 387.240 667.305 388.640 ;
        RECT 0.270 385.240 670.615 387.240 ;
        RECT 4.400 383.840 670.615 385.240 ;
        RECT 0.270 381.840 670.615 383.840 ;
        RECT 0.270 380.440 667.305 381.840 ;
        RECT 0.270 378.440 670.615 380.440 ;
        RECT 4.400 377.040 670.615 378.440 ;
        RECT 0.270 375.040 670.615 377.040 ;
        RECT 0.270 373.640 667.305 375.040 ;
        RECT 0.270 371.640 670.615 373.640 ;
        RECT 4.400 370.240 670.615 371.640 ;
        RECT 0.270 368.240 670.615 370.240 ;
        RECT 4.400 366.840 667.305 368.240 ;
        RECT 0.270 364.840 670.615 366.840 ;
        RECT 0.270 363.440 667.305 364.840 ;
        RECT 0.270 361.440 670.615 363.440 ;
        RECT 4.400 360.040 670.615 361.440 ;
        RECT 0.270 358.040 670.615 360.040 ;
        RECT 0.270 356.640 667.305 358.040 ;
        RECT 0.270 354.640 670.615 356.640 ;
        RECT 4.400 353.240 670.615 354.640 ;
        RECT 0.270 351.240 670.615 353.240 ;
        RECT 0.270 349.840 667.305 351.240 ;
        RECT 0.270 347.840 670.615 349.840 ;
        RECT 4.400 346.440 670.615 347.840 ;
        RECT 0.270 344.440 670.615 346.440 ;
        RECT 0.270 343.040 667.305 344.440 ;
        RECT 0.270 341.040 670.615 343.040 ;
        RECT 4.400 339.640 667.305 341.040 ;
        RECT 0.270 337.640 670.615 339.640 ;
        RECT 4.400 336.240 670.615 337.640 ;
        RECT 0.270 334.240 670.615 336.240 ;
        RECT 0.270 332.840 667.305 334.240 ;
        RECT 0.270 330.840 670.615 332.840 ;
        RECT 4.400 329.440 670.615 330.840 ;
        RECT 0.270 327.440 670.615 329.440 ;
        RECT 0.270 326.040 667.305 327.440 ;
        RECT 0.270 324.040 670.615 326.040 ;
        RECT 4.400 322.640 670.615 324.040 ;
        RECT 0.270 320.640 670.615 322.640 ;
        RECT 0.270 319.240 667.305 320.640 ;
        RECT 0.270 317.240 670.615 319.240 ;
        RECT 4.400 315.840 670.615 317.240 ;
        RECT 0.270 313.840 670.615 315.840 ;
        RECT 4.400 312.440 667.305 313.840 ;
        RECT 0.270 310.440 670.615 312.440 ;
        RECT 0.270 309.040 667.305 310.440 ;
        RECT 0.270 307.040 670.615 309.040 ;
        RECT 4.400 305.640 670.615 307.040 ;
        RECT 0.270 303.640 670.615 305.640 ;
        RECT 0.270 302.240 667.305 303.640 ;
        RECT 0.270 300.240 670.615 302.240 ;
        RECT 4.400 298.840 670.615 300.240 ;
        RECT 0.270 296.840 670.615 298.840 ;
        RECT 0.270 295.440 667.305 296.840 ;
        RECT 0.270 293.440 670.615 295.440 ;
        RECT 4.400 292.040 670.615 293.440 ;
        RECT 0.270 290.040 670.615 292.040 ;
        RECT 0.270 288.640 667.305 290.040 ;
        RECT 0.270 286.640 670.615 288.640 ;
        RECT 4.400 285.240 670.615 286.640 ;
        RECT 0.270 283.240 670.615 285.240 ;
        RECT 4.400 281.840 667.305 283.240 ;
        RECT 0.270 279.840 670.615 281.840 ;
        RECT 0.270 278.440 667.305 279.840 ;
        RECT 0.270 276.440 670.615 278.440 ;
        RECT 4.400 275.040 670.615 276.440 ;
        RECT 0.270 273.040 670.615 275.040 ;
        RECT 0.270 271.640 667.305 273.040 ;
        RECT 0.270 269.640 670.615 271.640 ;
        RECT 4.400 268.240 670.615 269.640 ;
        RECT 0.270 266.240 670.615 268.240 ;
        RECT 0.270 264.840 667.305 266.240 ;
        RECT 0.270 262.840 670.615 264.840 ;
        RECT 4.400 261.440 670.615 262.840 ;
        RECT 0.270 259.440 670.615 261.440 ;
        RECT 0.270 258.040 667.305 259.440 ;
        RECT 0.270 256.040 670.615 258.040 ;
        RECT 4.400 254.640 667.305 256.040 ;
        RECT 0.270 252.640 670.615 254.640 ;
        RECT 4.400 251.240 670.615 252.640 ;
        RECT 0.270 249.240 670.615 251.240 ;
        RECT 0.270 247.840 667.305 249.240 ;
        RECT 0.270 245.840 670.615 247.840 ;
        RECT 4.400 244.440 670.615 245.840 ;
        RECT 0.270 242.440 670.615 244.440 ;
        RECT 0.270 241.040 667.305 242.440 ;
        RECT 0.270 239.040 670.615 241.040 ;
        RECT 4.400 237.640 670.615 239.040 ;
        RECT 0.270 235.640 670.615 237.640 ;
        RECT 0.270 234.240 667.305 235.640 ;
        RECT 0.270 232.240 670.615 234.240 ;
        RECT 4.400 230.840 670.615 232.240 ;
        RECT 0.270 228.840 670.615 230.840 ;
        RECT 4.400 227.440 667.305 228.840 ;
        RECT 0.270 225.440 670.615 227.440 ;
        RECT 0.270 224.040 667.305 225.440 ;
        RECT 0.270 222.040 670.615 224.040 ;
        RECT 4.400 220.640 670.615 222.040 ;
        RECT 0.270 218.640 670.615 220.640 ;
        RECT 0.270 217.240 667.305 218.640 ;
        RECT 0.270 215.240 670.615 217.240 ;
        RECT 4.400 213.840 670.615 215.240 ;
        RECT 0.270 211.840 670.615 213.840 ;
        RECT 0.270 210.440 667.305 211.840 ;
        RECT 0.270 208.440 670.615 210.440 ;
        RECT 4.400 207.040 670.615 208.440 ;
        RECT 0.270 205.040 670.615 207.040 ;
        RECT 0.270 203.640 667.305 205.040 ;
        RECT 0.270 201.640 670.615 203.640 ;
        RECT 4.400 200.240 667.305 201.640 ;
        RECT 0.270 198.240 670.615 200.240 ;
        RECT 4.400 196.840 670.615 198.240 ;
        RECT 0.270 194.840 670.615 196.840 ;
        RECT 0.270 193.440 667.305 194.840 ;
        RECT 0.270 191.440 670.615 193.440 ;
        RECT 4.400 190.040 670.615 191.440 ;
        RECT 0.270 188.040 670.615 190.040 ;
        RECT 0.270 186.640 667.305 188.040 ;
        RECT 0.270 184.640 670.615 186.640 ;
        RECT 4.400 183.240 670.615 184.640 ;
        RECT 0.270 181.240 670.615 183.240 ;
        RECT 0.270 179.840 667.305 181.240 ;
        RECT 0.270 177.840 670.615 179.840 ;
        RECT 4.400 176.440 670.615 177.840 ;
        RECT 0.270 174.440 670.615 176.440 ;
        RECT 0.270 173.040 667.305 174.440 ;
        RECT 0.270 171.040 670.615 173.040 ;
        RECT 4.400 169.640 667.305 171.040 ;
        RECT 0.270 167.640 670.615 169.640 ;
        RECT 4.400 166.240 670.615 167.640 ;
        RECT 0.270 164.240 670.615 166.240 ;
        RECT 0.270 162.840 667.305 164.240 ;
        RECT 0.270 160.840 670.615 162.840 ;
        RECT 4.400 159.440 670.615 160.840 ;
        RECT 0.270 157.440 670.615 159.440 ;
        RECT 0.270 156.040 667.305 157.440 ;
        RECT 0.270 154.040 670.615 156.040 ;
        RECT 4.400 152.640 670.615 154.040 ;
        RECT 0.270 150.640 670.615 152.640 ;
        RECT 0.270 149.240 667.305 150.640 ;
        RECT 0.270 147.240 670.615 149.240 ;
        RECT 4.400 145.840 670.615 147.240 ;
        RECT 0.270 143.840 670.615 145.840 ;
        RECT 4.400 142.440 667.305 143.840 ;
        RECT 0.270 140.440 670.615 142.440 ;
        RECT 0.270 139.040 667.305 140.440 ;
        RECT 0.270 137.040 670.615 139.040 ;
        RECT 4.400 135.640 670.615 137.040 ;
        RECT 0.270 133.640 670.615 135.640 ;
        RECT 0.270 132.240 667.305 133.640 ;
        RECT 0.270 130.240 670.615 132.240 ;
        RECT 4.400 128.840 670.615 130.240 ;
        RECT 0.270 126.840 670.615 128.840 ;
        RECT 0.270 125.440 667.305 126.840 ;
        RECT 0.270 123.440 670.615 125.440 ;
        RECT 4.400 122.040 670.615 123.440 ;
        RECT 0.270 120.040 670.615 122.040 ;
        RECT 0.270 118.640 667.305 120.040 ;
        RECT 0.270 116.640 670.615 118.640 ;
        RECT 4.400 115.240 667.305 116.640 ;
        RECT 0.270 113.240 670.615 115.240 ;
        RECT 4.400 111.840 670.615 113.240 ;
        RECT 0.270 109.840 670.615 111.840 ;
        RECT 0.270 108.440 667.305 109.840 ;
        RECT 0.270 106.440 670.615 108.440 ;
        RECT 4.400 105.040 670.615 106.440 ;
        RECT 0.270 103.040 670.615 105.040 ;
        RECT 0.270 101.640 667.305 103.040 ;
        RECT 0.270 99.640 670.615 101.640 ;
        RECT 4.400 98.240 670.615 99.640 ;
        RECT 0.270 96.240 670.615 98.240 ;
        RECT 0.270 94.840 667.305 96.240 ;
        RECT 0.270 92.840 670.615 94.840 ;
        RECT 4.400 91.440 670.615 92.840 ;
        RECT 0.270 89.440 670.615 91.440 ;
        RECT 0.270 88.040 667.305 89.440 ;
        RECT 0.270 86.040 670.615 88.040 ;
        RECT 4.400 84.640 667.305 86.040 ;
        RECT 0.270 82.640 670.615 84.640 ;
        RECT 4.400 81.240 670.615 82.640 ;
        RECT 0.270 79.240 670.615 81.240 ;
        RECT 0.270 77.840 667.305 79.240 ;
        RECT 0.270 75.840 670.615 77.840 ;
        RECT 4.400 74.440 670.615 75.840 ;
        RECT 0.270 72.440 670.615 74.440 ;
        RECT 0.270 71.040 667.305 72.440 ;
        RECT 0.270 69.040 670.615 71.040 ;
        RECT 4.400 67.640 670.615 69.040 ;
        RECT 0.270 65.640 670.615 67.640 ;
        RECT 0.270 64.240 667.305 65.640 ;
        RECT 0.270 62.240 670.615 64.240 ;
        RECT 4.400 60.840 670.615 62.240 ;
        RECT 0.270 58.840 670.615 60.840 ;
        RECT 4.400 57.440 667.305 58.840 ;
        RECT 0.270 55.440 670.615 57.440 ;
        RECT 0.270 54.040 667.305 55.440 ;
        RECT 0.270 52.040 670.615 54.040 ;
        RECT 4.400 50.640 670.615 52.040 ;
        RECT 0.270 48.640 670.615 50.640 ;
        RECT 0.270 47.240 667.305 48.640 ;
        RECT 0.270 45.240 670.615 47.240 ;
        RECT 4.400 43.840 670.615 45.240 ;
        RECT 0.270 41.840 670.615 43.840 ;
        RECT 0.270 40.440 667.305 41.840 ;
        RECT 0.270 38.440 670.615 40.440 ;
        RECT 4.400 37.040 670.615 38.440 ;
        RECT 0.270 35.040 670.615 37.040 ;
        RECT 0.270 33.640 667.305 35.040 ;
        RECT 0.270 31.640 670.615 33.640 ;
        RECT 4.400 30.240 667.305 31.640 ;
        RECT 0.270 28.240 670.615 30.240 ;
        RECT 4.400 26.840 670.615 28.240 ;
        RECT 0.270 24.840 670.615 26.840 ;
        RECT 0.270 23.440 667.305 24.840 ;
        RECT 0.270 21.440 670.615 23.440 ;
        RECT 4.400 20.040 670.615 21.440 ;
        RECT 0.270 18.040 670.615 20.040 ;
        RECT 0.270 16.640 667.305 18.040 ;
        RECT 0.270 14.640 670.615 16.640 ;
        RECT 4.400 13.240 670.615 14.640 ;
        RECT 0.270 11.240 670.615 13.240 ;
        RECT 0.270 9.840 667.305 11.240 ;
        RECT 0.270 7.840 670.615 9.840 ;
        RECT 4.400 6.440 670.615 7.840 ;
        RECT 0.270 4.440 670.615 6.440 ;
        RECT 0.270 3.575 667.305 4.440 ;
      LAYER met4 ;
        RECT 0.295 12.415 20.640 664.865 ;
        RECT 23.040 12.415 97.440 664.865 ;
        RECT 99.840 12.415 174.240 664.865 ;
        RECT 176.640 12.415 251.040 664.865 ;
        RECT 253.440 12.415 327.840 664.865 ;
        RECT 330.240 12.415 404.640 664.865 ;
        RECT 407.040 12.415 481.440 664.865 ;
        RECT 483.840 12.415 558.240 664.865 ;
        RECT 560.640 12.415 635.040 664.865 ;
        RECT 637.440 12.415 664.865 664.865 ;
  END
END fft16_r2
END LIBRARY

